(* Logix 5000 Rung export; software revision 16.03; part 2 of 3 *)
(* tags used below, declared in another part *)
   AFC56 : AFC;
   AOI56AFC : AOI56AFC;
(* AOI56AFC, continued *)

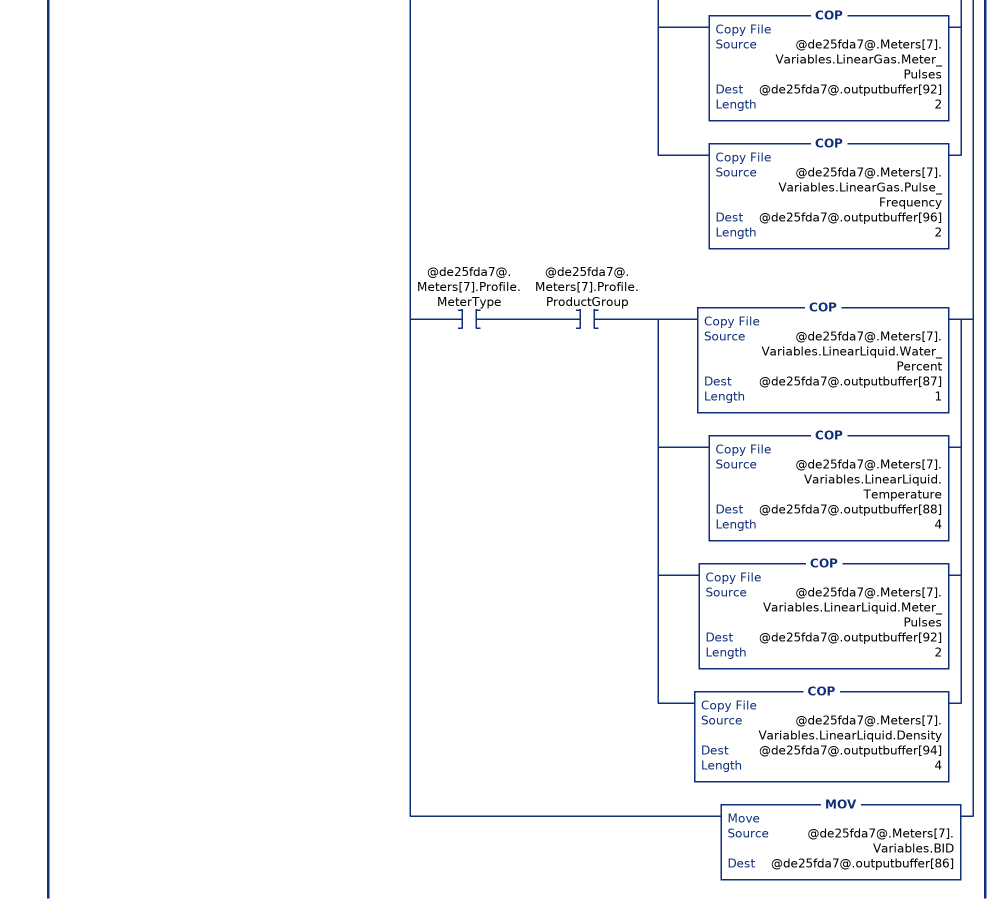
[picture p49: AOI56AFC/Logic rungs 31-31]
   31: XIO(@de25fda7@.Flags.AFC_Set_Clock)LIM(1,@de25fda7@.CycleCounter,16)[ADD(8,8192,@de25fda7@.Meters[7].Variables.BID) ,XIO(@de25fda7@.EnableStatus.Meter8) [OTE(@de25fda7@.Meters[7].Variables.BID.8) ,OTU(@de25fda7@.DisableMeter.Meter8) ] ,XIC(@de25fda7@.EnableStatus.Meter8) OTU(@de25fda7@.EnableMeter.Meter8) ,XIO(@de25fda7@.Meters[7].Profile.MeterType) XIO(@de25fda7@.Meters[7].Profile.ProductGroup) COP(@de25fda7@.Meters[7].Variables.DifferentialGas.Temperature,@de25fda7@.outputbuffer[88],6) ,XIO(@de25fda7@.Meters[7].Profile.MeterType) XIC(@de25fda7@.Meters[7].Profile.ProductGroup) [COP(@de25fda7@.Meters[7].Variables.DifferentialLiquid.Water_Percent,@de25fda7@.outputbuffer[87],1) ,COP(@de25fda7@.Meters[7].Variables.DifferentialLiquid.Temperature,@de25fda7@.outputbuffer[88],8) ] ,XIC(@de25fda7@.Meters[7].Profile.MeterType) XIO(@de25fda7@.Meters[7].Profile.ProductGroup) [COP(@de25fda7@.Meters[7].Variables.LinearGas.Temperature,@de25fda7@.outputbuffer[88],4) ,COP(@de25fda7@.Meters[7].Variables.LinearGas.Meter_Pulses,@de25fda7@.outputbuffer[92],2) ,COP(@de25fda7@.Meters[7].Variables.LinearGas.Pulse_Frequency,@de25fda7@.outputbuffer[96],2) ] ,XIC(@de25fda7@.Meters[7].Profile.MeterType) XIC(@de25fda7@.Meters[7].Profile.ProductGroup) [COP(@de25fda7@.Meters[7].Variables.LinearLiquid.Water_Percent,@de25fda7@.outputbuffer[87],1) ,COP(@de25fda7@.Meters[7].Variables.LinearLiquid.Temperature,@de25fda7@.outputbuffer[88],4) ,COP(@de25fda7@.Meters[7].Variables.LinearLiquid.Meter_Pulses,@de25fda7@.outputbuffer[92],2) ,COP(@de25fda7@.Meters[7].Variables.LinearLiquid.Density,@de25fda7@.outputbuffer[94],4) ] ,MOV(@de25fda7@.Meters[7].Variables.BID,@de25fda7@.outputbuffer[86]) ];
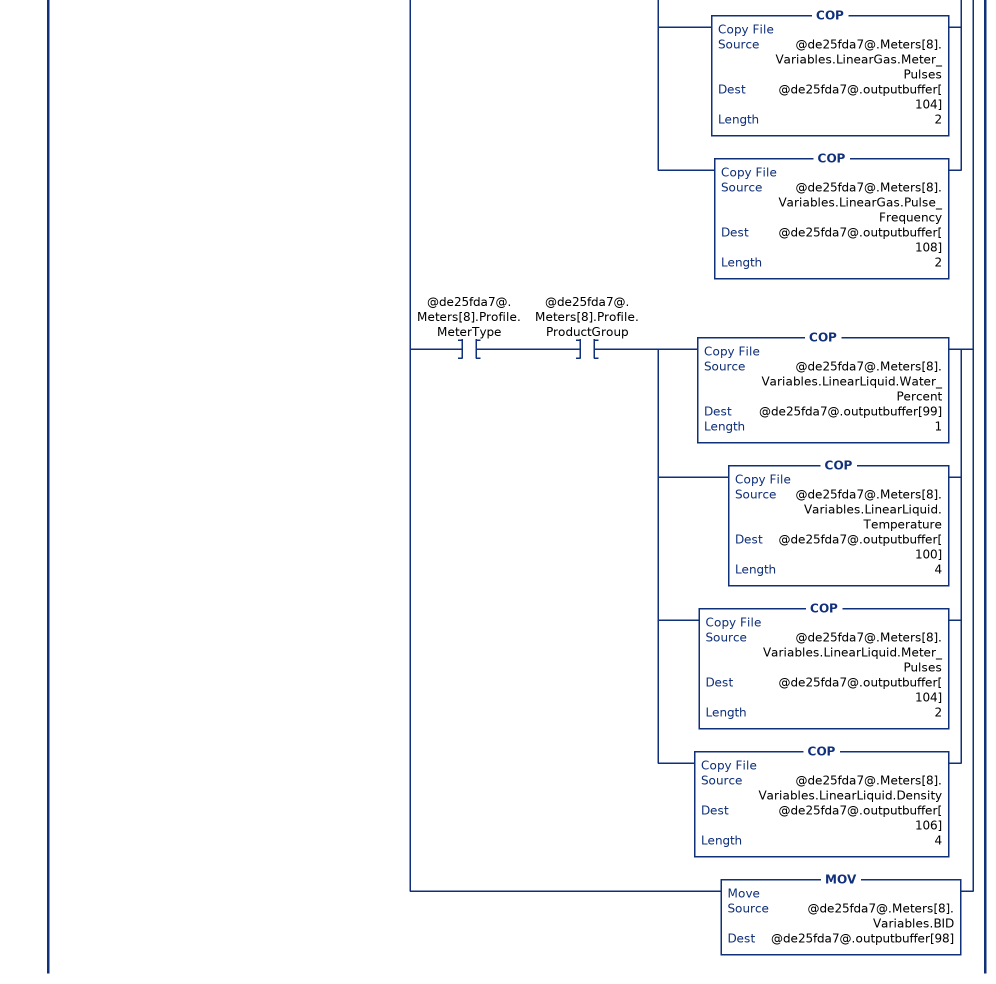
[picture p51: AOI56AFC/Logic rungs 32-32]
   32: XIO(@de25fda7@.Flags.AFC_Set_Clock)LIM(1,@de25fda7@.CycleCounter,16)[ADD(9,8192,@de25fda7@.Meters[8].Variables.BID) ,XIO(@de25fda7@.EnableStatus.Meter9) [OTE(@de25fda7@.Meters[8].Variables.BID.8) ,OTU(@de25fda7@.DisableMeter.Meter9) ] ,XIC(@de25fda7@.EnableStatus.Meter9) OTU(@de25fda7@.EnableMeter.Meter9) ,XIO(@de25fda7@.Meters[8].Profile.MeterType) XIO(@de25fda7@.Meters[8].Profile.ProductGroup) COP(@de25fda7@.Meters[8].Variables.DifferentialGas.Temperature,@de25fda7@.outputbuffer[100],6) ,XIO(@de25fda7@.Meters[8].Profile.MeterType) XIC(@de25fda7@.Meters[8].Profile.ProductGroup) [COP(@de25fda7@.Meters[8].Variables.DifferentialLiquid.Water_Percent,@de25fda7@.outputbuffer[99],1) ,COP(@de25fda7@.Meters[8].Variables.DifferentialLiquid.Temperature,@de25fda7@.outputbuffer[100],8) ] ,XIC(@de25fda7@.Meters[8].Profile.MeterType) XIO(@de25fda7@.Meters[8].Profile.ProductGroup) [COP(@de25fda7@.Meters[8].Variables.LinearGas.Temperature,@de25fda7@.outputbuffer[100],4) ,COP(@de25fda7@.Meters[8].Variables.LinearGas.Meter_Pulses,@de25fda7@.outputbuffer[104],2) ,COP(@de25fda7@.Meters[8].Variables.LinearGas.Pulse_Frequency,@de25fda7@.outputbuffer[108],2) ] ,XIC(@de25fda7@.Meters[8].Profile.MeterType) XIC(@de25fda7@.Meters[8].Profile.ProductGroup) [COP(@de25fda7@.Meters[8].Variables.LinearLiquid.Water_Percent,@de25fda7@.outputbuffer[99],1) ,COP(@de25fda7@.Meters[8].Variables.LinearLiquid.Temperature,@de25fda7@.outputbuffer[100],4) ,COP(@de25fda7@.Meters[8].Variables.LinearLiquid.Meter_Pulses,@de25fda7@.outputbuffer[104],2) ,COP(@de25fda7@.Meters[8].Variables.LinearLiquid.Density,@de25fda7@.outputbuffer[106],4) ] ,MOV(@de25fda7@.Meters[8].Variables.BID,@de25fda7@.outputbuffer[98]) ];
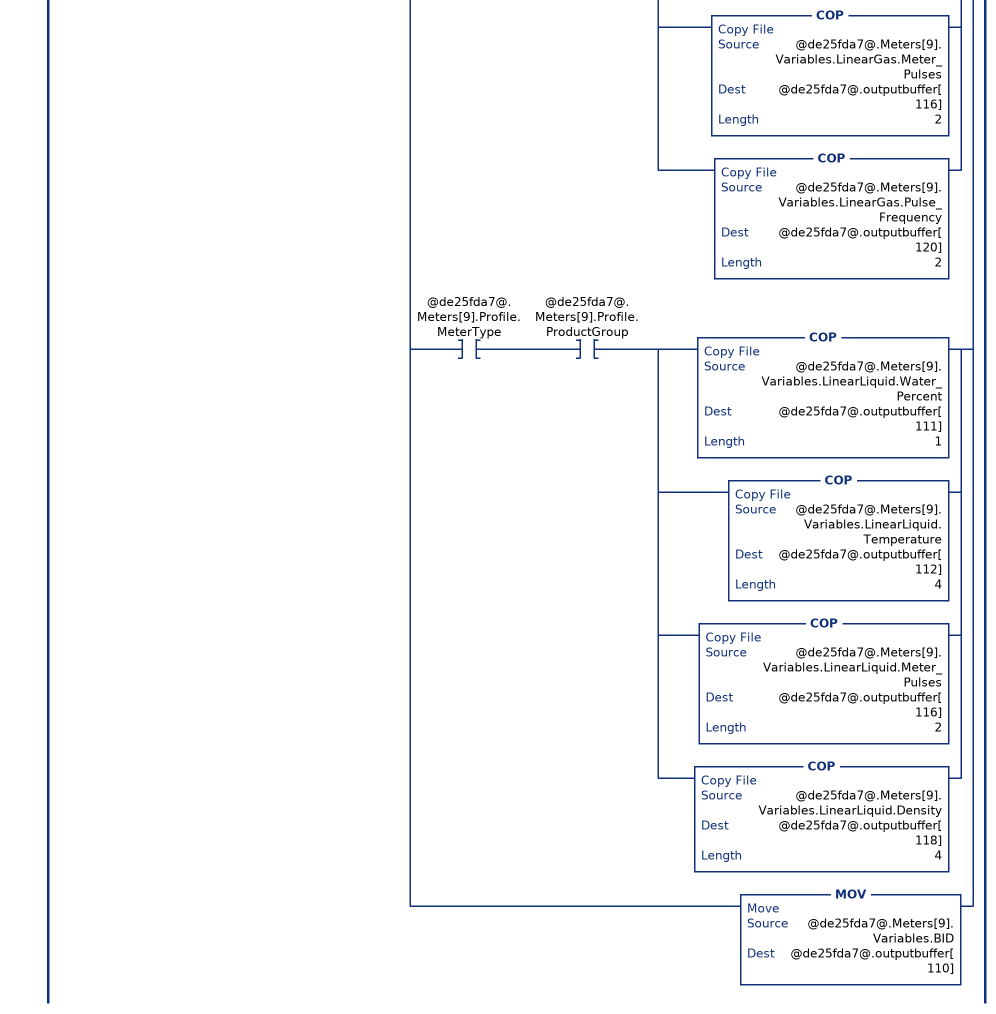
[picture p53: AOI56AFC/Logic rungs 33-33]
   33: XIO(@de25fda7@.Flags.AFC_Set_Clock)LIM(1,@de25fda7@.CycleCounter,16)[ADD(10,8192,@de25fda7@.Meters[9].Variables.BID) ,XIO(@de25fda7@.EnableStatus.Meter10) [OTE(@de25fda7@.Meters[9].Variables.BID.8) ,OTU(@de25fda7@.DisableMeter.Meter10) ] ,XIC(@de25fda7@.EnableStatus.Meter10) OTU(@de25fda7@.EnableMeter.Meter10) ,XIO(@de25fda7@.Meters[9].Profile.MeterType) XIO(@de25fda7@.Meters[9].Profile.ProductGroup) COP(@de25fda7@.Meters[9].Variables.DifferentialGas.Temperature,@de25fda7@.outputbuffer[112],6) ,XIO(@de25fda7@.Meters[9].Profile.MeterType) XIC(@de25fda7@.Meters[9].Profile.ProductGroup) [COP(@de25fda7@.Meters[9].Variables.DifferentialLiquid.Water_Percent,@de25fda7@.outputbuffer[111],1) ,COP(@de25fda7@.Meters[9].Variables.DifferentialLiquid.Temperature,@de25fda7@.outputbuffer[112],8) ] ,XIC(@de25fda7@.Meters[9].Profile.MeterType) XIO(@de25fda7@.Meters[9].Profile.ProductGroup) [COP(@de25fda7@.Meters[9].Variables.LinearGas.Temperature,@de25fda7@.outputbuffer[112],4) ,COP(@de25fda7@.Meters[9].Variables.LinearGas.Meter_Pulses,@de25fda7@.outputbuffer[116],2) ,COP(@de25fda7@.Meters[9].Variables.LinearGas.Pulse_Frequency,@de25fda7@.outputbuffer[120],2) ] ,XIC(@de25fda7@.Meters[9].Profile.MeterType) XIC(@de25fda7@.Meters[9].Profile.ProductGroup) [COP(@de25fda7@.Meters[9].Variables.LinearLiquid.Water_Percent,@de25fda7@.outputbuffer[111],1) ,COP(@de25fda7@.Meters[9].Variables.LinearLiquid.Temperature,@de25fda7@.outputbuffer[112],4) ,COP(@de25fda7@.Meters[9].Variables.LinearLiquid.Meter_Pulses,@de25fda7@.outputbuffer[116],2) ,COP(@de25fda7@.Meters[9].Variables.LinearLiquid.Density,@de25fda7@.outputbuffer[118],4) ] ,MOV(@de25fda7@.Meters[9].Variables.BID,@de25fda7@.outputbuffer[110]) ];
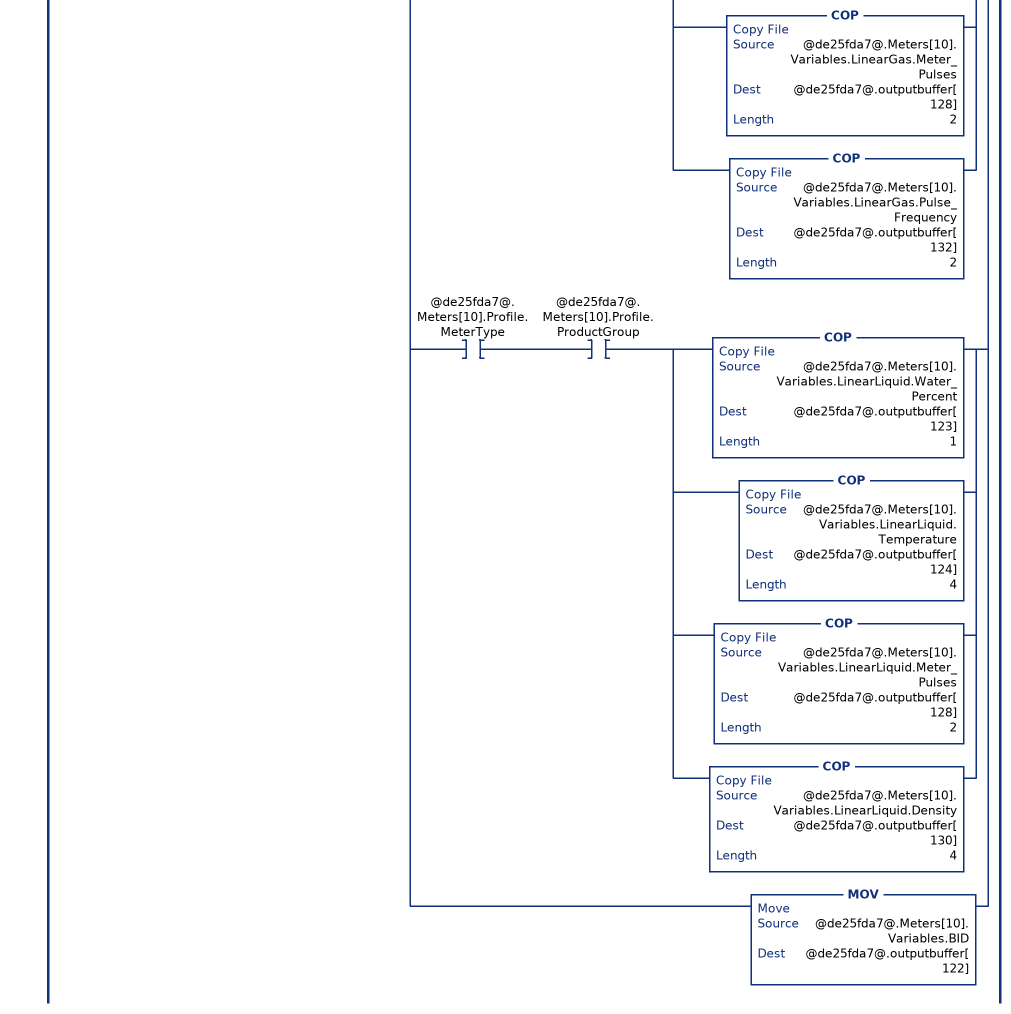
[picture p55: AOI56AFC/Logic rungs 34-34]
   34: XIO(@de25fda7@.Flags.AFC_Set_Clock)LIM(1,@de25fda7@.CycleCounter,16)[ADD(11,8192,@de25fda7@.Meters[10].Variables.BID) ,XIO(@de25fda7@.EnableStatus.Meter11) [OTE(@de25fda7@.Meters[10].Variables.BID.8) ,OTU(@de25fda7@.DisableMeter.Meter11) ] ,XIC(@de25fda7@.EnableStatus.Meter11) OTU(@de25fda7@.EnableMeter.Meter11) ,XIO(@de25fda7@.Meters[10].Profile.MeterType) XIO(@de25fda7@.Meters[10].Profile.ProductGroup) COP(@de25fda7@.Meters[10].Variables.DifferentialGas.Temperature,@de25fda7@.outputbuffer[124],6) ,XIO(@de25fda7@.Meters[10].Profile.MeterType) XIC(@de25fda7@.Meters[10].Profile.ProductGroup) [COP(@de25fda7@.Meters[10].Variables.DifferentialLiquid.Water_Percent,@de25fda7@.outputbuffer[123],1) ,COP(@de25fda7@.Meters[10].Variables.DifferentialLiquid.Temperature,@de25fda7@.outputbuffer[124],8) ] ,XIC(@de25fda7@.Meters[10].Profile.MeterType) XIO(@de25fda7@.Meters[10].Profile.ProductGroup) [COP(@de25fda7@.Meters[10].Variables.LinearGas.Temperature,@de25fda7@.outputbuffer[124],4) ,COP(@de25fda7@.Meters[10].Variables.LinearGas.Meter_Pulses,@de25fda7@.outputbuffer[128],2) ,COP(@de25fda7@.Meters[10].Variables.LinearGas.Pulse_Frequency,@de25fda7@.outputbuffer[132],2) ] ,XIC(@de25fda7@.Meters[10].Profile.MeterType) XIC(@de25fda7@.Meters[10].Profile.ProductGroup) [COP(@de25fda7@.Meters[10].Variables.LinearLiquid.Water_Percent,@de25fda7@.outputbuffer[123],1) ,COP(@de25fda7@.Meters[10].Variables.LinearLiquid.Temperature,@de25fda7@.outputbuffer[124],4) ,COP(@de25fda7@.Meters[10].Variables.LinearLiquid.Meter_Pulses,@de25fda7@.outputbuffer[128],2) ,COP(@de25fda7@.Meters[10].Variables.LinearLiquid.Density,@de25fda7@.outputbuffer[130],4) ] ,MOV(@de25fda7@.Meters[10].Variables.BID,@de25fda7@.outputbuffer[122]) ];
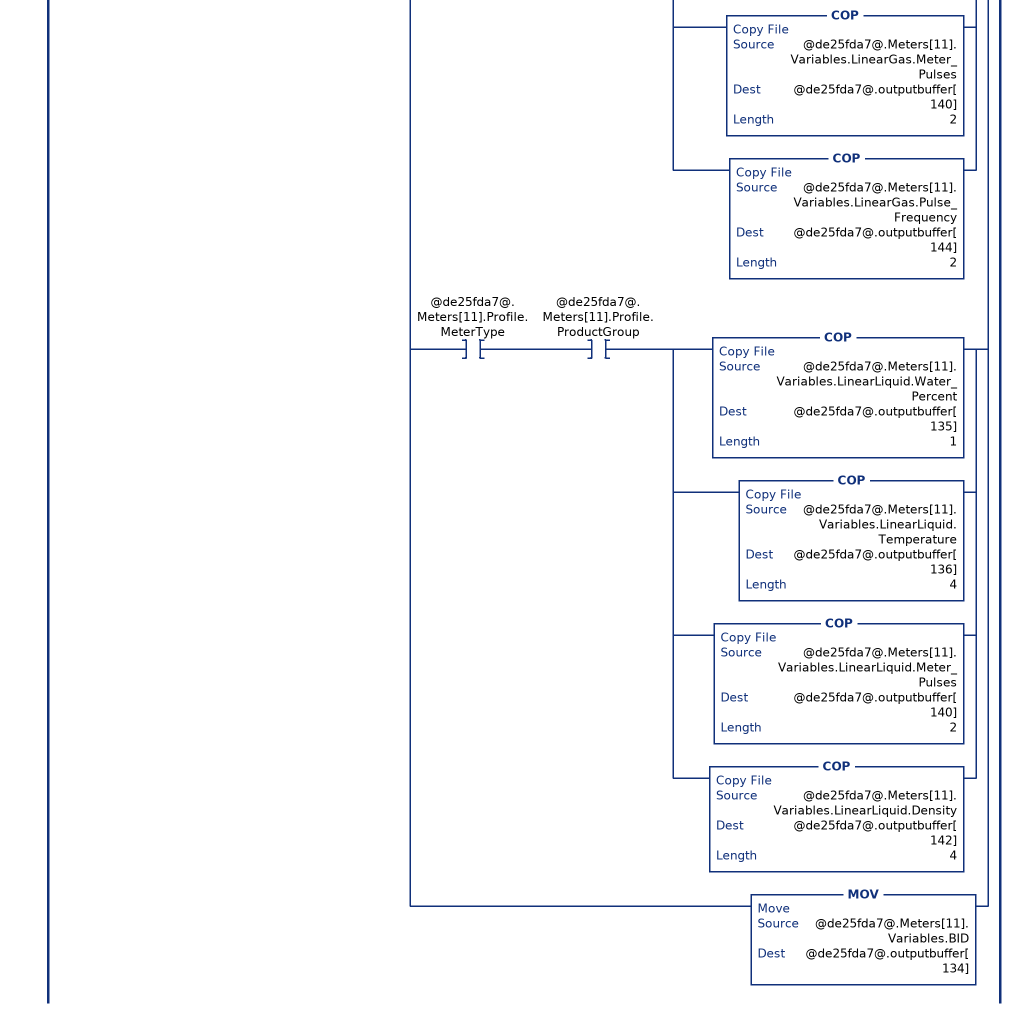
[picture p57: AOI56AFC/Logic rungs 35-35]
   35: XIO(@de25fda7@.Flags.AFC_Set_Clock)LIM(1,@de25fda7@.CycleCounter,16)[ADD(12,8192,@de25fda7@.Meters[11].Variables.BID) ,XIO(@de25fda7@.EnableStatus.Meter12) [OTE(@de25fda7@.Meters[11].Variables.BID.8) ,OTU(@de25fda7@.DisableMeter.Meter12) ] ,XIC(@de25fda7@.EnableStatus.Meter12) OTU(@de25fda7@.EnableMeter.Meter12) ,XIO(@de25fda7@.Meters[11].Profile.MeterType) XIO(@de25fda7@.Meters[11].Profile.ProductGroup) COP(@de25fda7@.Meters[11].Variables.DifferentialGas.Temperature,@de25fda7@.outputbuffer[136],6) ,XIO(@de25fda7@.Meters[11].Profile.MeterType) XIC(@de25fda7@.Meters[11].Profile.ProductGroup) [COP(@de25fda7@.Meters[11].Variables.DifferentialLiquid.Water_Percent,@de25fda7@.outputbuffer[135],1) ,COP(@de25fda7@.Meters[11].Variables.DifferentialLiquid.Temperature,@de25fda7@.outputbuffer[136],8) ] ,XIC(@de25fda7@.Meters[11].Profile.MeterType) XIO(@de25fda7@.Meters[11].Profile.ProductGroup) [COP(@de25fda7@.Meters[11].Variables.LinearGas.Temperature,@de25fda7@.outputbuffer[136],4) ,COP(@de25fda7@.Meters[11].Variables.LinearGas.Meter_Pulses,@de25fda7@.outputbuffer[140],2) ,COP(@de25fda7@.Meters[11].Variables.LinearGas.Pulse_Frequency,@de25fda7@.outputbuffer[144],2) ] ,XIC(@de25fda7@.Meters[11].Profile.MeterType) XIC(@de25fda7@.Meters[11].Profile.ProductGroup) [COP(@de25fda7@.Meters[11].Variables.LinearLiquid.Water_Percent,@de25fda7@.outputbuffer[135],1) ,COP(@de25fda7@.Meters[11].Variables.LinearLiquid.Temperature,@de25fda7@.outputbuffer[136],4) ,COP(@de25fda7@.Meters[11].Variables.LinearLiquid.Meter_Pulses,@de25fda7@.outputbuffer[140],2) ,COP(@de25fda7@.Meters[11].Variables.LinearLiquid.Density,@de25fda7@.outputbuffer[142],4) ] ,MOV(@de25fda7@.Meters[11].Variables.BID,@de25fda7@.outputbuffer[134]) ];
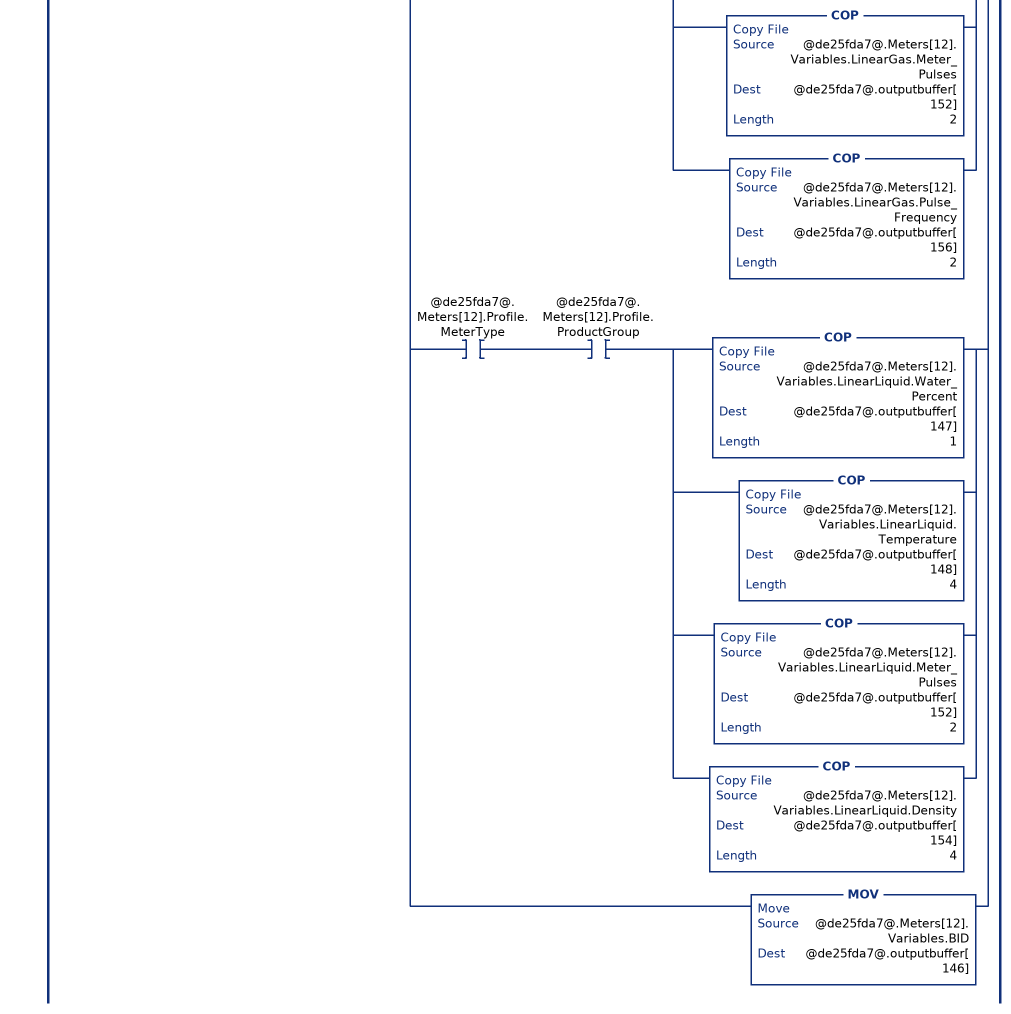
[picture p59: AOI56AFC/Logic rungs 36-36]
   36: XIO(@de25fda7@.Flags.AFC_Set_Clock)LIM(1,@de25fda7@.CycleCounter,16)[ADD(13,8192,@de25fda7@.Meters[12].Variables.BID) ,XIO(@de25fda7@.EnableStatus.Meter13) [OTE(@de25fda7@.Meters[12].Variables.BID.8) ,OTU(@de25fda7@.DisableMeter.Meter13) ] ,XIC(@de25fda7@.EnableStatus.Meter13) OTU(@de25fda7@.EnableMeter.Meter13) ,XIO(@de25fda7@.Meters[12].Profile.MeterType) XIO(@de25fda7@.Meters[12].Profile.ProductGroup) COP(@de25fda7@.Meters[12].Variables.DifferentialGas.Temperature,@de25fda7@.outputbuffer[148],6) ,XIO(@de25fda7@.Meters[12].Profile.MeterType) XIC(@de25fda7@.Meters[12].Profile.ProductGroup) [COP(@de25fda7@.Meters[12].Variables.DifferentialLiquid.Water_Percent,@de25fda7@.outputbuffer[147],1) ,COP(@de25fda7@.Meters[12].Variables.DifferentialLiquid.Temperature,@de25fda7@.outputbuffer[148],8) ] ,XIC(@de25fda7@.Meters[12].Profile.MeterType) XIO(@de25fda7@.Meters[12].Profile.ProductGroup) [COP(@de25fda7@.Meters[12].Variables.LinearGas.Temperature,@de25fda7@.outputbuffer[148],4) ,COP(@de25fda7@.Meters[12].Variables.LinearGas.Meter_Pulses,@de25fda7@.outputbuffer[152],2) ,COP(@de25fda7@.Meters[12].Variables.LinearGas.Pulse_Frequency,@de25fda7@.outputbuffer[156],2) ] ,XIC(@de25fda7@.Meters[12].Profile.MeterType) XIC(@de25fda7@.Meters[12].Profile.ProductGroup) [COP(@de25fda7@.Meters[12].Variables.LinearLiquid.Water_Percent,@de25fda7@.outputbuffer[147],1) ,COP(@de25fda7@.Meters[12].Variables.LinearLiquid.Temperature,@de25fda7@.outputbuffer[148],4) ,COP(@de25fda7@.Meters[12].Variables.LinearLiquid.Meter_Pulses,@de25fda7@.outputbuffer[152],2) ,COP(@de25fda7@.Meters[12].Variables.LinearLiquid.Density,@de25fda7@.outputbuffer[154],4) ] ,MOV(@de25fda7@.Meters[12].Variables.BID,@de25fda7@.outputbuffer[146]) ];
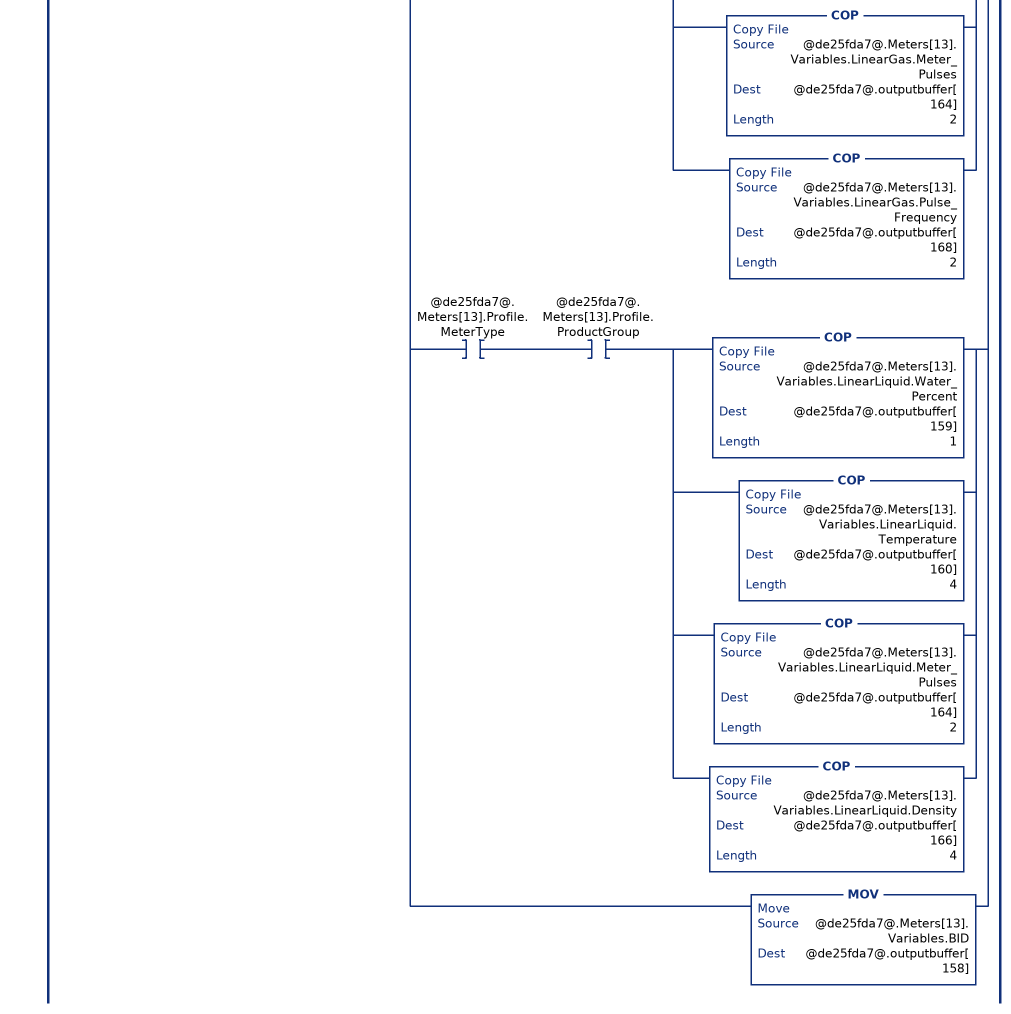
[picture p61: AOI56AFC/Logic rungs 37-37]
   37: XIO(@de25fda7@.Flags.AFC_Set_Clock)LIM(1,@de25fda7@.CycleCounter,16)[ADD(14,8192,@de25fda7@.Meters[13].Variables.BID) ,XIO(@de25fda7@.EnableStatus.Meter14) [OTE(@de25fda7@.Meters[13].Variables.BID.8) ,OTU(@de25fda7@.DisableMeter.Meter14) ] ,XIC(@de25fda7@.EnableStatus.Meter14) OTU(@de25fda7@.EnableMeter.Meter14) ,XIO(@de25fda7@.Meters[13].Profile.MeterType) XIO(@de25fda7@.Meters[13].Profile.ProductGroup) COP(@de25fda7@.Meters[13].Variables.DifferentialGas.Temperature,@de25fda7@.outputbuffer[160],6) ,XIO(@de25fda7@.Meters[13].Profile.MeterType) XIC(@de25fda7@.Meters[13].Profile.ProductGroup) [COP(@de25fda7@.Meters[13].Variables.DifferentialLiquid.Water_Percent,@de25fda7@.outputbuffer[159],1) ,COP(@de25fda7@.Meters[13].Variables.DifferentialLiquid.Temperature,@de25fda7@.outputbuffer[160],8) ] ,XIC(@de25fda7@.Meters[13].Profile.MeterType) XIO(@de25fda7@.Meters[13].Profile.ProductGroup) [COP(@de25fda7@.Meters[13].Variables.LinearGas.Temperature,@de25fda7@.outputbuffer[160],4) ,COP(@de25fda7@.Meters[13].Variables.LinearGas.Meter_Pulses,@de25fda7@.outputbuffer[164],2) ,COP(@de25fda7@.Meters[13].Variables.LinearGas.Pulse_Frequency,@de25fda7@.outputbuffer[168],2) ] ,XIC(@de25fda7@.Meters[13].Profile.MeterType) XIC(@de25fda7@.Meters[13].Profile.ProductGroup) [COP(@de25fda7@.Meters[13].Variables.LinearLiquid.Water_Percent,@de25fda7@.outputbuffer[159],1) ,COP(@de25fda7@.Meters[13].Variables.LinearLiquid.Temperature,@de25fda7@.outputbuffer[160],4) ,COP(@de25fda7@.Meters[13].Variables.LinearLiquid.Meter_Pulses,@de25fda7@.outputbuffer[164],2) ,COP(@de25fda7@.Meters[13].Variables.LinearLiquid.Density,@de25fda7@.outputbuffer[166],4) ] ,MOV(@de25fda7@.Meters[13].Variables.BID,@de25fda7@.outputbuffer[158]) ];
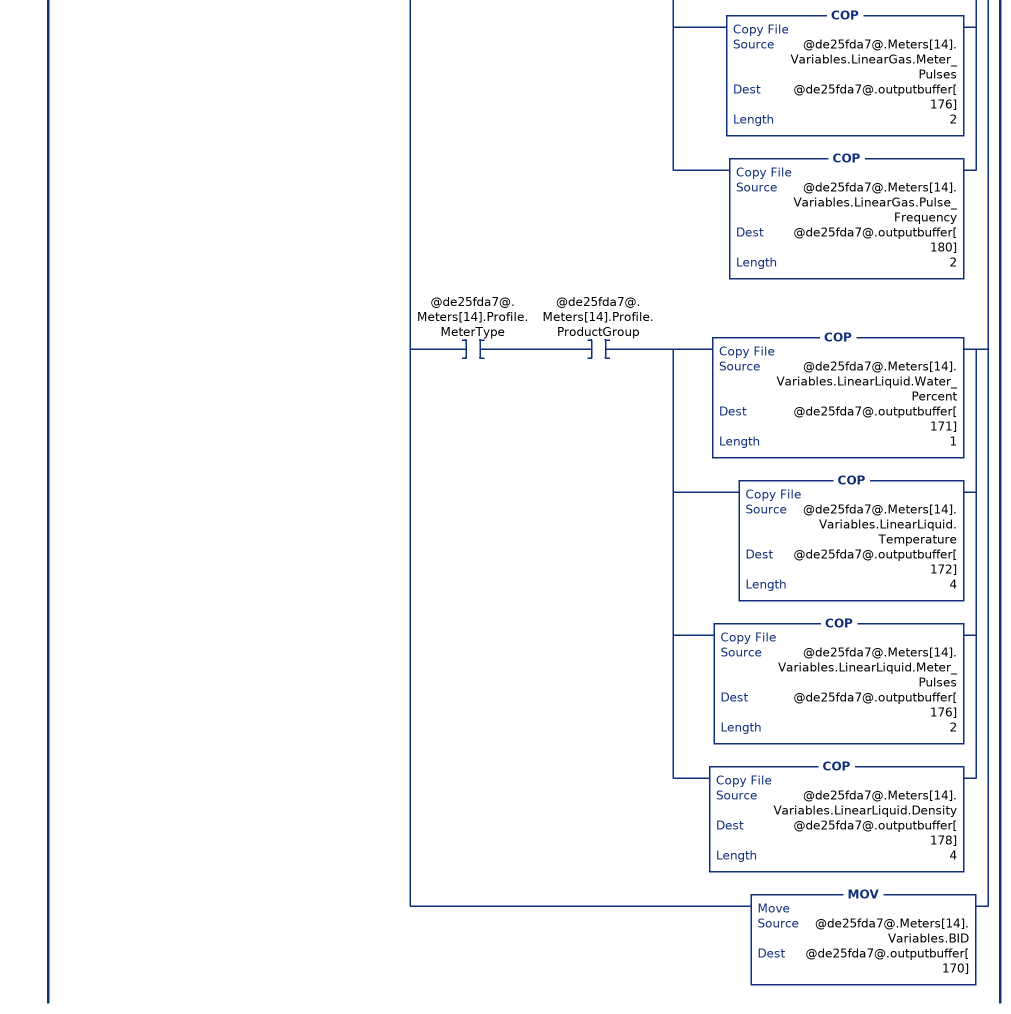
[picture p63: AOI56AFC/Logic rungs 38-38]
   38: XIO(@de25fda7@.Flags.AFC_Set_Clock)LIM(1,@de25fda7@.CycleCounter,16)[ADD(15,8192,@de25fda7@.Meters[14].Variables.BID) ,XIO(@de25fda7@.EnableStatus.Meter15) [OTE(@de25fda7@.Meters[14].Variables.BID.8) ,OTU(@de25fda7@.DisableMeter.Meter15) ] ,XIC(@de25fda7@.EnableStatus.Meter15) OTU(@de25fda7@.EnableMeter.Meter15) ,XIO(@de25fda7@.Meters[14].Profile.MeterType) XIO(@de25fda7@.Meters[14].Profile.ProductGroup) COP(@de25fda7@.Meters[14].Variables.DifferentialGas.Temperature,@de25fda7@.outputbuffer[172],6) ,XIO(@de25fda7@.Meters[14].Profile.MeterType) XIC(@de25fda7@.Meters[14].Profile.ProductGroup) [COP(@de25fda7@.Meters[14].Variables.DifferentialLiquid.Water_Percent,@de25fda7@.outputbuffer[171],1) ,COP(@de25fda7@.Meters[14].Variables.DifferentialLiquid.Temperature,@de25fda7@.outputbuffer[172],8) ] ,XIC(@de25fda7@.Meters[14].Profile.MeterType) XIO(@de25fda7@.Meters[14].Profile.ProductGroup) [COP(@de25fda7@.Meters[14].Variables.LinearGas.Temperature,@de25fda7@.outputbuffer[172],4) ,COP(@de25fda7@.Meters[14].Variables.LinearGas.Meter_Pulses,@de25fda7@.outputbuffer[176],2) ,COP(@de25fda7@.Meters[14].Variables.LinearGas.Pulse_Frequency,@de25fda7@.outputbuffer[180],2) ] ,XIC(@de25fda7@.Meters[14].Profile.MeterType) XIC(@de25fda7@.Meters[14].Profile.ProductGroup) [COP(@de25fda7@.Meters[14].Variables.LinearLiquid.Water_Percent,@de25fda7@.outputbuffer[171],1) ,COP(@de25fda7@.Meters[14].Variables.LinearLiquid.Temperature,@de25fda7@.outputbuffer[172],4) ,COP(@de25fda7@.Meters[14].Variables.LinearLiquid.Meter_Pulses,@de25fda7@.outputbuffer[176],2) ,COP(@de25fda7@.Meters[14].Variables.LinearLiquid.Density,@de25fda7@.outputbuffer[178],4) ] ,MOV(@de25fda7@.Meters[14].Variables.BID,@de25fda7@.outputbuffer[170]) ];
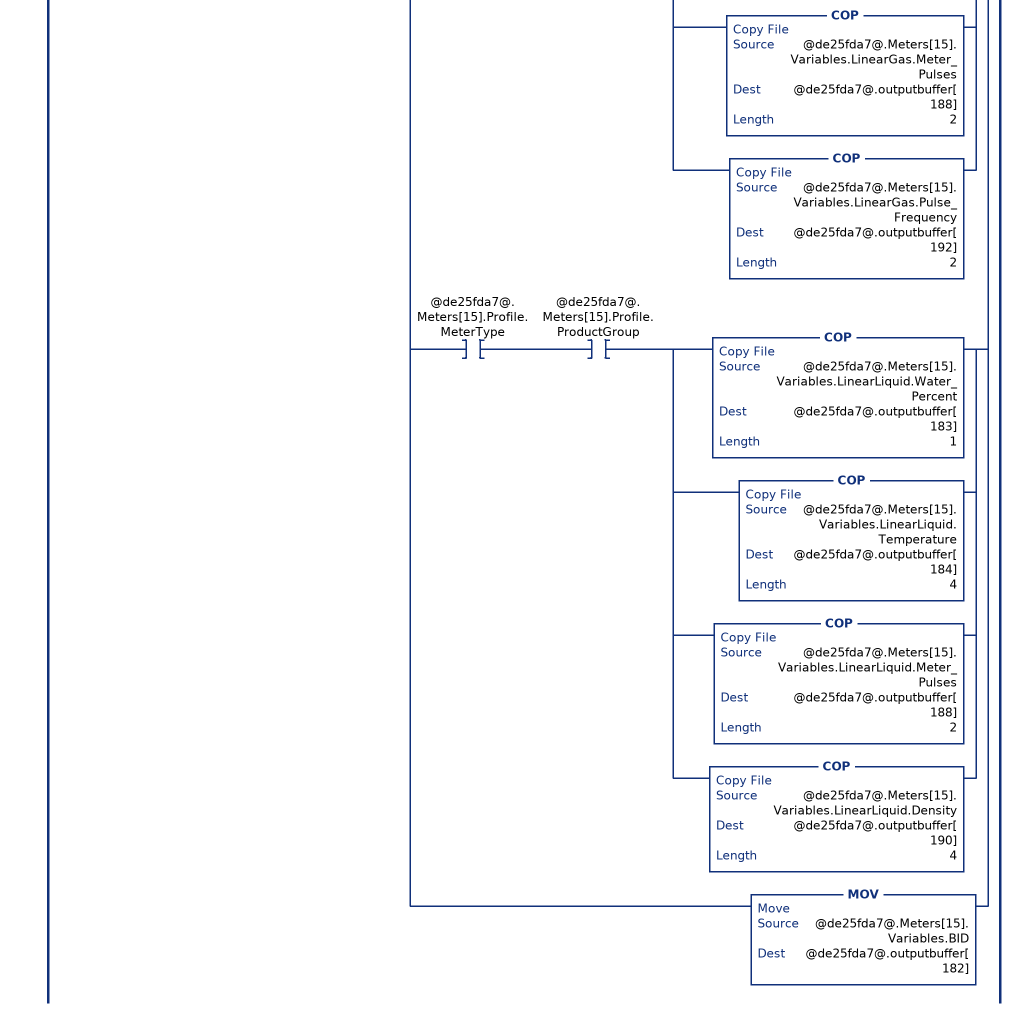
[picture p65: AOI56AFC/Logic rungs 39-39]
   39: XIO(@de25fda7@.Flags.AFC_Set_Clock)LIM(1,@de25fda7@.CycleCounter,16)[ADD(16,8192,@de25fda7@.Meters[15].Variables.BID) ,XIO(@de25fda7@.EnableStatus.Meter16) [OTE(@de25fda7@.Meters[15].Variables.BID.8) ,OTU(@de25fda7@.DisableMeter.Meter16) ] ,XIC(@de25fda7@.EnableStatus.Meter16) OTU(@de25fda7@.EnableMeter.Meter16) ,XIO(@de25fda7@.Meters[15].Profile.MeterType) XIO(@de25fda7@.Meters[15].Profile.ProductGroup) COP(@de25fda7@.Meters[15].Variables.DifferentialGas.Temperature,@de25fda7@.outputbuffer[184],6) ,XIO(@de25fda7@.Meters[15].Profile.MeterType) XIC(@de25fda7@.Meters[15].Profile.ProductGroup) [COP(@de25fda7@.Meters[15].Variables.DifferentialLiquid.Water_Percent,@de25fda7@.outputbuffer[183],1) ,COP(@de25fda7@.Meters[15].Variables.DifferentialLiquid.Temperature,@de25fda7@.outputbuffer[184],8) ] ,XIC(@de25fda7@.Meters[15].Profile.MeterType) XIO(@de25fda7@.Meters[15].Profile.ProductGroup) [COP(@de25fda7@.Meters[15].Variables.LinearGas.Temperature,@de25fda7@.outputbuffer[184],4) ,COP(@de25fda7@.Meters[15].Variables.LinearGas.Meter_Pulses,@de25fda7@.outputbuffer[188],2) ,COP(@de25fda7@.Meters[15].Variables.LinearGas.Pulse_Frequency,@de25fda7@.outputbuffer[192],2) ] ,XIC(@de25fda7@.Meters[15].Profile.MeterType) XIC(@de25fda7@.Meters[15].Profile.ProductGroup) [COP(@de25fda7@.Meters[15].Variables.LinearLiquid.Water_Percent,@de25fda7@.outputbuffer[183],1) ,COP(@de25fda7@.Meters[15].Variables.LinearLiquid.Temperature,@de25fda7@.outputbuffer[184],4) ,COP(@de25fda7@.Meters[15].Variables.LinearLiquid.Meter_Pulses,@de25fda7@.outputbuffer[188],2) ,COP(@de25fda7@.Meters[15].Variables.LinearLiquid.Density,@de25fda7@.outputbuffer[190],4) ] ,MOV(@de25fda7@.Meters[15].Variables.BID,@de25fda7@.outputbuffer[182]) ];
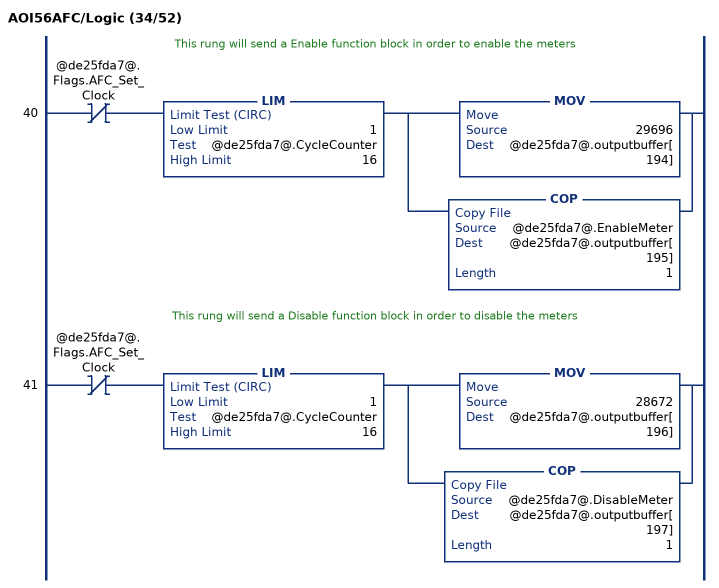
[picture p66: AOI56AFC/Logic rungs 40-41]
   // This rung will send a Enable function block in order to enable the meters
   40: XIO(@de25fda7@.Flags.AFC_Set_Clock)LIM(1,@de25fda7@.CycleCounter,16)[MOV(29696,@de25fda7@.outputbuffer[194]) ,COP(@de25fda7@.EnableMeter,@de25fda7@.outputbuffer[195],1) ];
   // This rung will send a Disable function block in order to disable the meters
   41: XIO(@de25fda7@.Flags.AFC_Set_Clock)LIM(1,@de25fda7@.CycleCounter,16)[MOV(28672,@de25fda7@.outputbuffer[196]) ,COP(@de25fda7@.DisableMeter,@de25fda7@.outputbuffer[197],1) ];
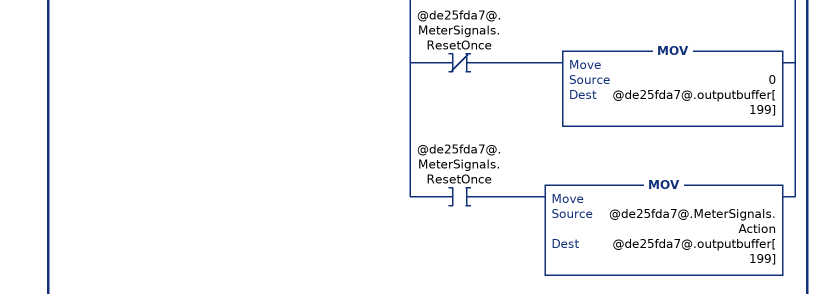
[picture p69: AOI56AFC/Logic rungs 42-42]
   // This rung will allow the ladder logic to reset any accumulator or to write a daily or hourly archive
   42: XIO(@de25fda7@.Flags.AFC_Set_Clock)LIM(1,@de25fda7@.CycleCounter,16)[ADD(12288,@de25fda7@.MeterSignals.Meter,@de25fda7@.MeterSignals.BID) ,XIO(@de25fda7@.MeterSignals.Enable) OTE(@de25fda7@.MeterSignals.BID.8) ,XIC(@de25fda7@.MeterSignals.Signals.Sel_Stream1) [OTL(@de25fda7@.MeterSignals.Action.0) ,OTU(@de25fda7@.MeterSignals.Signals.Sel_Stream1) ] ,XIC(@de25fda7@.MeterSignals.Signals.Sel_Stream2) [OTL(@de25fda7@.MeterSignals.Action.1) ,OTU(@de25fda7@.MeterSignals.Signals.Sel_Stream2) ] ,XIC(@de25fda7@.MeterSignals.Signals.Sel_Stream3) [OTL(@de25fda7@.MeterSignals.Action.2) ,OTU(@de25fda7@.MeterSignals.Signals.Sel_Stream3) ] ,XIC(@de25fda7@.MeterSignals.Signals.Sel_Stream4) [OTL(@de25fda7@.MeterSignals.Action.3) ,OTU(@de25fda7@.MeterSignals.Signals.Sel_Stream4) ] ,XIC(@de25fda7@.MeterSignals.Signals.Res_Acc1) [OTL(@de25fda7@.MeterSignals.Action.4) ,OTU(@de25fda7@.MeterSignals.Signals.Res_Acc1) ] ,XIC(@de25fda7@.MeterSignals.Signals.Res_Acc2) [OTL(@de25fda7@.MeterSignals.Action.5) ,OTU(@de25fda7@.MeterSignals.Signals.Res_Acc2) ] ,XIC(@de25fda7@.MeterSignals.Signals.Res_Acc3) [OTL(@de25fda7@.MeterSignals.Action.6) ,OTU(@de25fda7@.MeterSignals.Signals.Res_Acc3) ] ,XIC(@de25fda7@.MeterSignals.Signals.Res_Acc4) [OTL(@de25fda7@.MeterSignals.Action.7) ,OTU(@de25fda7@.MeterSignals.Signals.Res_Acc4) ] ,XIC(@de25fda7@.MeterSignals.Signals.Wr_Daily_Archive) [OTL(@de25fda7@.MeterSignals.Action.8) ,OTU(@de25fda7@.MeterSignals.Signals.Wr_Daily_Archive) ] ,XIC(@de25fda7@.MeterSignals.Signals.Wr_Hrly_Archive) [OTL(@de25fda7@.MeterSignals.Action.9) ,OTU(@de25fda7@.MeterSignals.Signals.Wr_Hrly_Archive) ] ,MOV(@de25fda7@.MeterSignals.BID,@de25fda7@.outputbuffer[198]) ,XIO(@de25fda7@.MeterSignals.ResetOnce) MOV(0,@de25fda7@.outputbuffer[199]) ,XIC(@de25fda7@.MeterSignals.ResetOnce) MOV(@de25fda7@.MeterSignals.Action,@de25fda7@.outputbuffer[199]) ];
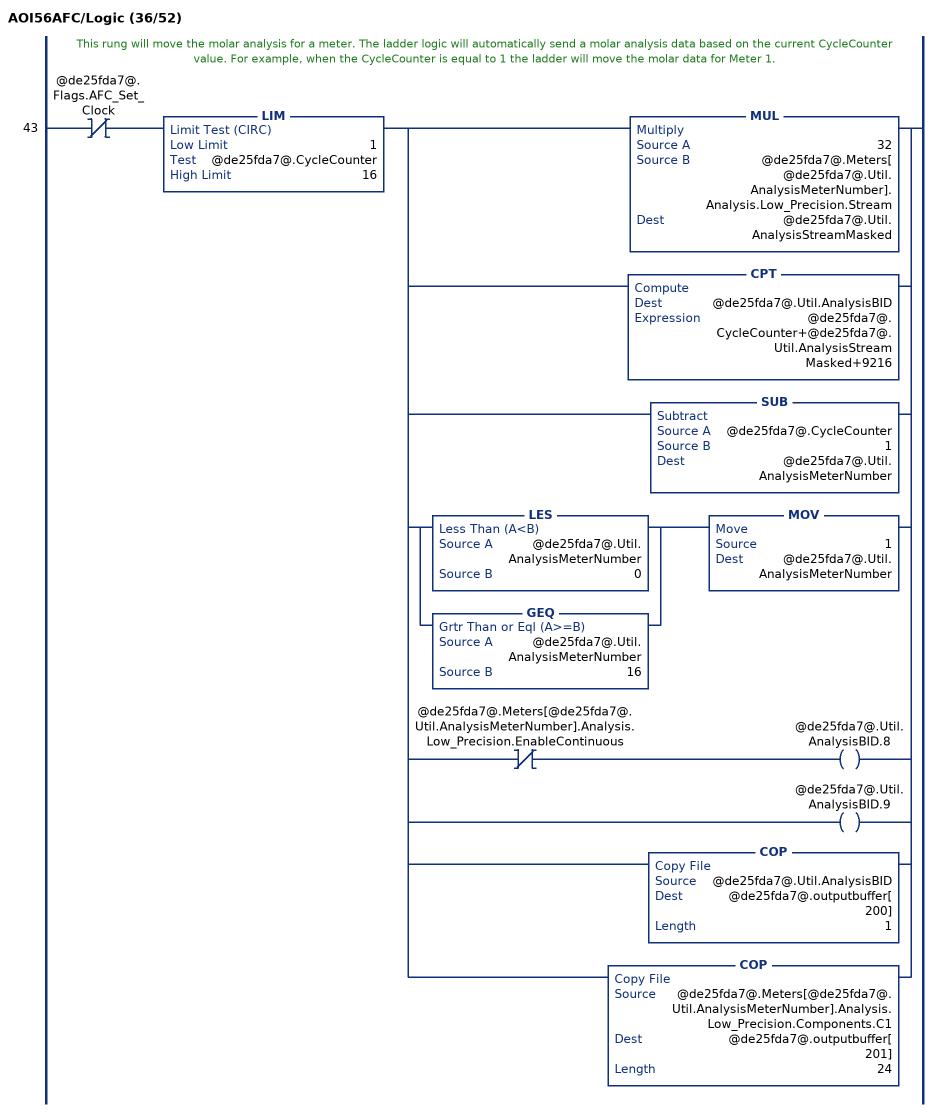
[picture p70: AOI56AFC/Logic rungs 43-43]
   // This rung will move the molar analysis for a meter. The ladder logic will automatically send a molar analysis data based on the current CycleCounter value. For example, when the CycleCounter is equal to 1 the ladder will move the molar data for Meter 1.
   43: XIO(@de25fda7@.Flags.AFC_Set_Clock)LIM(1,@de25fda7@.CycleCounter,16)[MUL(32,@de25fda7@.Meters[@de25fda7@.Util.AnalysisMeterNumber].Analysis.Low_Precision.Stream,@de25fda7@.Util.AnalysisStreamMasked) ,CPT(@de25fda7@.Util.AnalysisBID,@de25fda7@.CycleCounter+@de25fda7@.Util.AnalysisStreamMasked+9216) ,SUB(@de25fda7@.CycleCounter,1,@de25fda7@.Util.AnalysisMeterNumber) ,[LES(@de25fda7@.Util.AnalysisMeterNumber,0) ,GEQ(@de25fda7@.Util.AnalysisMeterNumber,16) ] MOV(1,@de25fda7@.Util.AnalysisMeterNumber) ,XIO(@de25fda7@.Meters[@de25fda7@.Util.AnalysisMeterNumber].Analysis.Low_Precision.EnableContinuous) OTE(@de25fda7@.Util.AnalysisBID.8) ,OTE(@de25fda7@.Util.AnalysisBID.9) ,COP(@de25fda7@.Util.AnalysisBID,@de25fda7@.outputbuffer[200],1) ,COP(@de25fda7@.Meters[@de25fda7@.Util.AnalysisMeterNumber].Analysis.Low_Precision.Components.C1,@de25fda7@.outputbuffer[201],24) ];
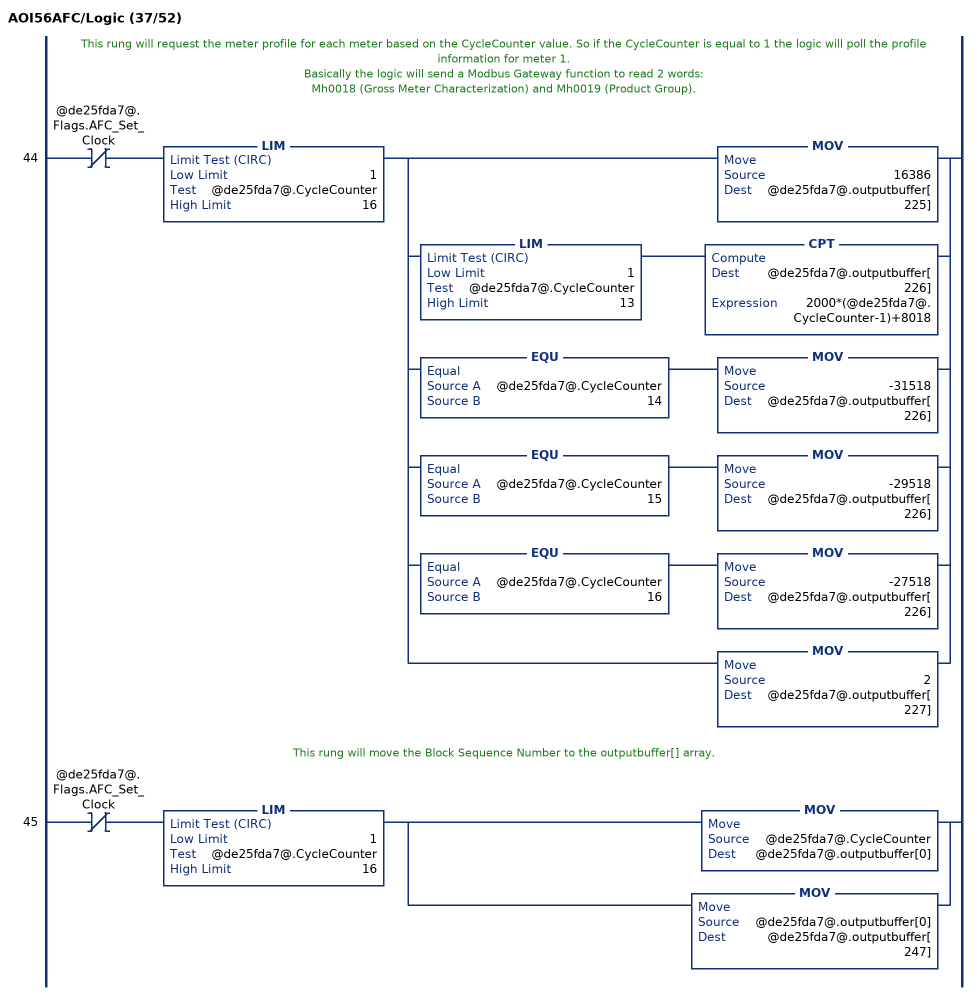
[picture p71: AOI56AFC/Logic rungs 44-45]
   // This rung will request the meter profile for each meter based on the CycleCounter value. So if the CycleCounter is equal to 1 the logic will poll the profile information for meter 1.
   // Basically the logic will send a Modbus Gateway function to read 2 words:
   // Mh0018 (Gross Meter Characterization) and Mh0019 (Product Group).
   44: XIO(@de25fda7@.Flags.AFC_Set_Clock)LIM(1,@de25fda7@.CycleCounter,16)[MOV(16386,@de25fda7@.outputbuffer[225]) ,LIM(1,@de25fda7@.CycleCounter,13) CPT(@de25fda7@.outputbuffer[226],2000*(@de25fda7@.CycleCounter-1)+8018) ,EQU(@de25fda7@.CycleCounter,14) MOV(-31518,@de25fda7@.outputbuffer[226]) ,EQU(@de25fda7@.CycleCounter,15) MOV(-29518,@de25fda7@.outputbuffer[226]) ,EQU(@de25fda7@.CycleCounter,16) MOV(-27518,@de25fda7@.outputbuffer[226]) ,MOV(2,@de25fda7@.outputbuffer[227]) ];
   // This rung will move the Block Sequence Number to the outputbuffer[] array.
   45: XIO(@de25fda7@.Flags.AFC_Set_Clock)LIM(1,@de25fda7@.CycleCounter,16)[MOV(@de25fda7@.CycleCounter,@de25fda7@.outputbuffer[0]) ,MOV(@de25fda7@.outputbuffer[0],@de25fda7@.outputbuffer[247]) ];
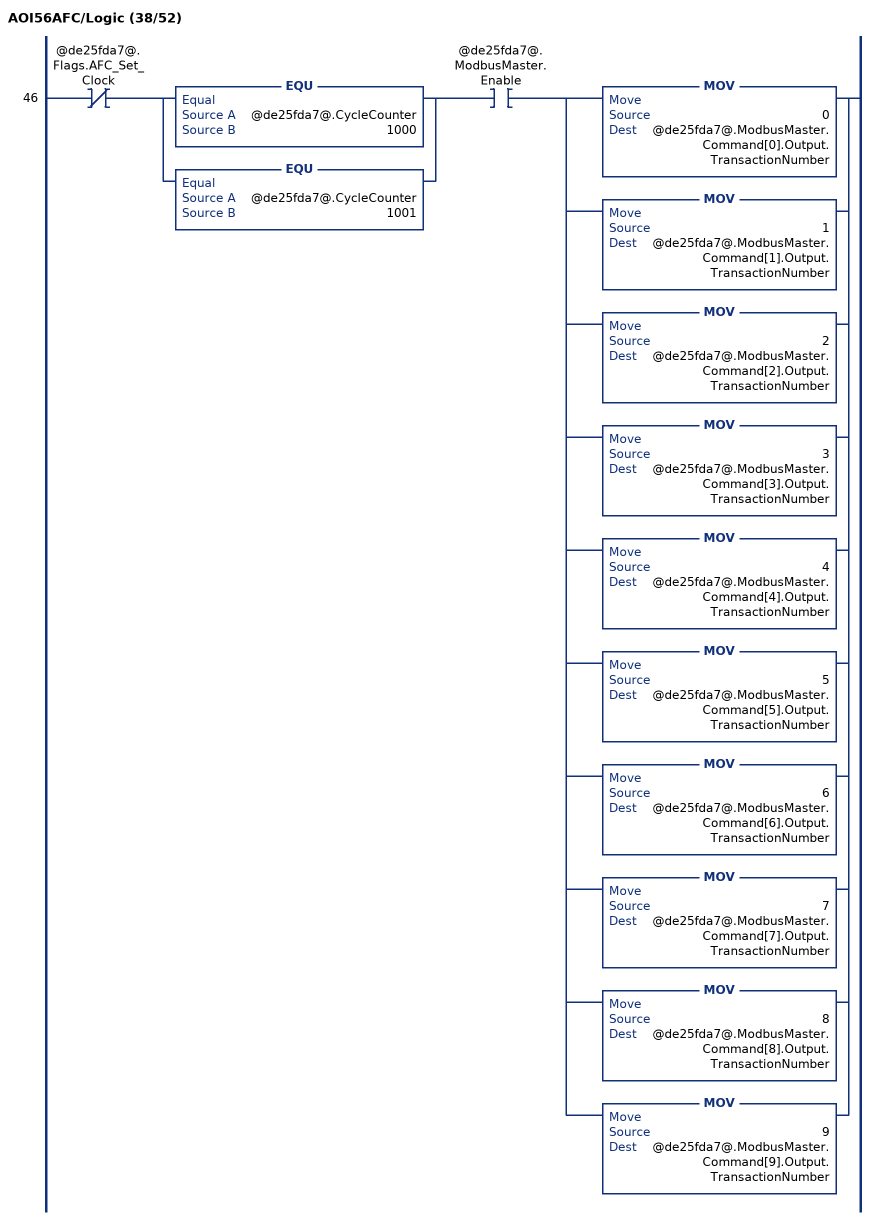
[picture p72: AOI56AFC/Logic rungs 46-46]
   46: XIO(@de25fda7@.Flags.AFC_Set_Clock)[EQU(@de25fda7@.CycleCounter,1000) ,EQU(@de25fda7@.CycleCounter,1001) ]XIC(@de25fda7@.ModbusMaster.Enable)[MOV(0,@de25fda7@.ModbusMaster.Command[0].Output.TransactionNumber) ,MOV(1,@de25fda7@.ModbusMaster.Command[1].Output.TransactionNumber) ,MOV(2,@de25fda7@.ModbusMaster.Command[2].Output.TransactionNumber) ,MOV(3,@de25fda7@.ModbusMaster.Command[3].Output.TransactionNumber) ,MOV(4,@de25fda7@.ModbusMaster.Command[4].Output.TransactionNumber) ,MOV(5,@de25fda7@.ModbusMaster.Command[5].Output.TransactionNumber) ,MOV(6,@de25fda7@.ModbusMaster.Command[6].Output.TransactionNumber) ,MOV(7,@de25fda7@.ModbusMaster.Command[7].Output.TransactionNumber) ,MOV(8,@de25fda7@.ModbusMaster.Command[8].Output.TransactionNumber) ,MOV(9,@de25fda7@.ModbusMaster.Command[9].Output.TransactionNumber) ];
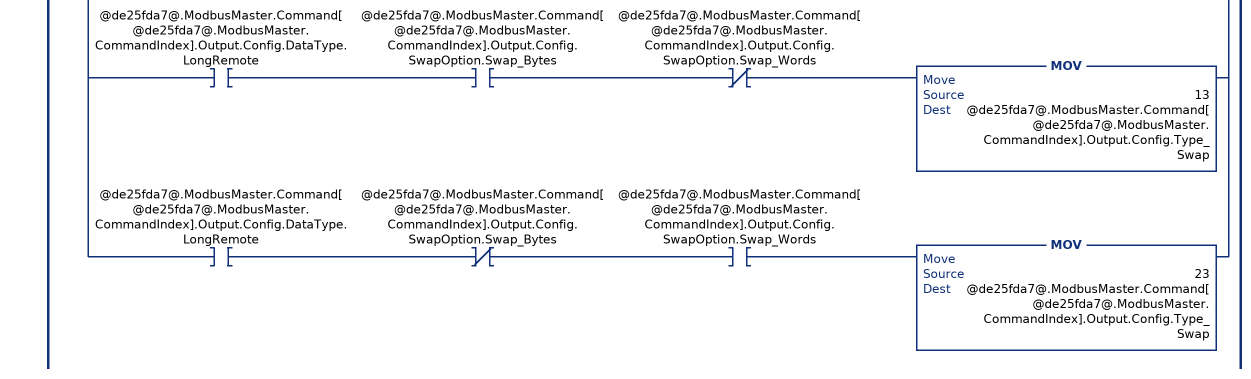
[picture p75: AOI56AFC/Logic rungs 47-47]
   // This handles the Modbus Master logic
   47: XIO(@de25fda7@.Flags.AFC_Set_Clock)[EQU(@de25fda7@.CycleCounter,1000) ,EQU(@de25fda7@.CycleCounter,1001) ]XIC(@de25fda7@.ModbusMaster.Enable)[[MOV(24576,@de25fda7@.ModbusMaster.Command[@de25fda7@.ModbusMaster.CommandIndex].Output.BOD) ,ADD(@de25fda7@.ModbusMaster.Command[@de25fda7@.ModbusMaster.CommandIndex].Output.BOD,130,@de25fda7@.ModbusMaster.Command[@de25fda7@.ModbusMaster.CommandIndex].Output.BOD) ] ,XIC(@de25fda7@.ModbusMaster.Command[@de25fda7@.ModbusMaster.CommandIndex].Output.Config.FunctionType_Write) OTE(@de25fda7@.ModbusMaster.Command[@de25fda7@.ModbusMaster.CommandIndex].Output.BOD.11) ,XIO(@de25fda7@.ModbusMaster.Command[@de25fda7@.ModbusMaster.CommandIndex].Output.Config.Enable) OTE(@de25fda7@.ModbusMaster.Command[@de25fda7@.ModbusMaster.CommandIndex].Output.BOD.8) ,XIC(@de25fda7@.ModbusMaster.Command[@de25fda7@.ModbusMaster.CommandIndex].Output.Config.RegisterBank_Input) OTE(@de25fda7@.ModbusMaster.Command[@de25fda7@.ModbusMaster.CommandIndex].Output.BOD.10) ,XIC(@de25fda7@.ModbusMaster.Command[@de25fda7@.ModbusMaster.CommandIndex].Output.Config.DataType.Bit) MOV(0,@de25fda7@.ModbusMaster.Command[@de25fda7@.ModbusMaster.CommandIndex].Output.Config.Type_Swap) ,XIC(@de25fda7@.ModbusMaster.Command[@de25fda7@.ModbusMaster.CommandIndex].Output.Config.DataType.Word) XIO(@de25fda7@.ModbusMaster.Command[@de25fda7@.ModbusMaster.CommandIndex].Output.Config.SwapOption.Swap_Bytes) MOV(1,@de25fda7@.ModbusMaster.Command[@de25fda7@.ModbusMaster.CommandIndex].Output.Config.Type_Swap) ,XIC(@de25fda7@.ModbusMaster.Command[@de25fda7@.ModbusMaster.CommandIndex].Output.Config.DataType.Word) XIC(@de25fda7@.ModbusMaster.Command[@de25fda7@.ModbusMaster.CommandIndex].Output.Config.SwapOption.Swap_Bytes) MOV(11,@de25fda7@.ModbusMaster.Command[@de25fda7@.ModbusMaster.CommandIndex].Output.Config.Type_Swap) ,XIC(@de25fda7@.ModbusMaster.Command[@de25fda7@.ModbusMaster.CommandIndex].Output.Config.DataType.Long) XIO(@de25fda7@.ModbusMaster.Command[@de25fda7@.ModbusMaster.CommandIndex].Output.Config.SwapOption.Swap_Bytes) XIO(@de25fda7@.ModbusMaster.Command[@de25fda7@.ModbusMaster.CommandIndex].Output.Config.SwapOption.Swap_Words) MOV(2,@de25fda7@.ModbusMaster.Command[@de25fda7@.ModbusMaster.CommandIndex].Output.Config.Type_Swap) ,XIC(@de25fda7@.ModbusMaster.Command[@de25fda7@.ModbusMaster.CommandIndex].Output.Config.DataType.Long) XIC(@de25fda7@.ModbusMaster.Command[@de25fda7@.ModbusMaster.CommandIndex].Output.Config.SwapOption.Swap_Bytes) XIO(@de25fda7@.ModbusMaster.Command[@de25fda7@.ModbusMaster.CommandIndex].Output.Config.SwapOption.Swap_Words) MOV(12,@de25fda7@.ModbusMaster.Command[@de25fda7@.ModbusMaster.CommandIndex].Output.Config.Type_Swap) ,XIC(@de25fda7@.ModbusMaster.Command[@de25fda7@.ModbusMaster.CommandIndex].Output.Config.DataType.Long) XIO(@de25fda7@.ModbusMaster.Command[@de25fda7@.ModbusMaster.CommandIndex].Output.Config.SwapOption.Swap_Bytes) XIC(@de25fda7@.ModbusMaster.Command[@de25fda7@.ModbusMaster.CommandIndex].Output.Config.SwapOption.Swap_Words) MOV(22,@de25fda7@.ModbusMaster.Command[@de25fda7@.ModbusMaster.CommandIndex].Output.Config.Type_Swap) ,XIC(@de25fda7@.ModbusMaster.Command[@de25fda7@.ModbusMaster.CommandIndex].Output.Config.DataType.LongRemote) XIO(@de25fda7@.ModbusMaster.Command[@de25fda7@.ModbusMaster.CommandIndex].Output.Config.SwapOption.Swap_Bytes) XIO(@de25fda7@.ModbusMaster.Command[@de25fda7@.ModbusMaster.CommandIndex].Output.Config.SwapOption.Swap_Words) MOV(3,@de25fda7@.ModbusMaster.Command[@de25fda7@.ModbusMaster.CommandIndex].Output.Config.Type_Swap) ,XIC(@de25fda7@.ModbusMaster.Command[@de25fda7@.ModbusMaster.CommandIndex].Output.Config.DataType.LongRemote) XIC(@de25fda7@.ModbusMaster.Command[@de25fda7@.ModbusMaster.CommandIndex].Output.Config.SwapOption.Swap_Bytes) XIO(@de25fda7@.ModbusMaster.Command[@de25fda7@.ModbusMaster.CommandIndex].Output.Config.SwapOption.Swap_Words) MOV(13,@de25fda7@.ModbusMaster.Command[@de25fda7@.ModbusMaster.CommandIndex].Output.Config.Type_Swap) ,XIC(@de25fda7@.ModbusMaster.Command[@de25fda7@.ModbusMaster.CommandIndex].Output.Config.DataType.LongRemote) XIO(@de25fda7@.ModbusMaster.Command[@de25fda7@.ModbusMaster.CommandIndex].Output.Config.SwapOption.Swap_Bytes) XIC(@de25fda7@.ModbusMaster.Command[@de25fda7@.ModbusMaster.CommandIndex].Output.Config.SwapOption.Swap_Words) MOV(23,@de25fda7@.ModbusMaster.Command[@de25fda7@.ModbusMaster.CommandIndex].Output.Config.Type_Swap) ];
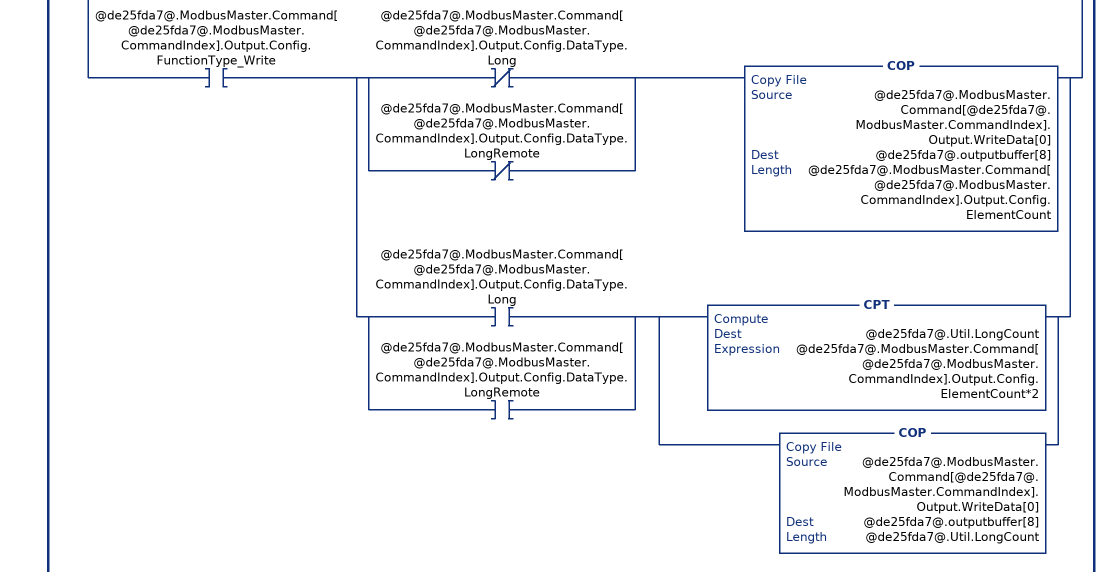
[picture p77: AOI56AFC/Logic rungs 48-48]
   48: XIO(@de25fda7@.Flags.AFC_Set_Clock)[EQU(@de25fda7@.CycleCounter,1000) ,EQU(@de25fda7@.CycleCounter,1001) ]XIC(@de25fda7@.ModbusMaster.Enable)[MOV(131,@de25fda7@.outputbuffer[1]) ,MOV(@de25fda7@.ModbusMaster.Command[@de25fda7@.ModbusMaster.CommandIndex].Output.BOD,@de25fda7@.outputbuffer[2]) ,MOV(@de25fda7@.ModbusMaster.Command[@de25fda7@.ModbusMaster.CommandIndex].Output.TransactionNumber,@de25fda7@.outputbuffer[3]) ,MOV(@de25fda7@.ModbusMaster.Command[@de25fda7@.ModbusMaster.CommandIndex].Output.Config.Type_Swap,@de25fda7@.outputbuffer[4]) ,MOV(@de25fda7@.ModbusMaster.Command[@de25fda7@.ModbusMaster.CommandIndex].Output.Config.SlaveAddress,@de25fda7@.outputbuffer[5]) ,MOV(@de25fda7@.ModbusMaster.Command[@de25fda7@.ModbusMaster.CommandIndex].Output.Config.ModbusAddress,@de25fda7@.outputbuffer[6]) ,MOV(@de25fda7@.ModbusMaster.Command[@de25fda7@.ModbusMaster.CommandIndex].Output.Config.ElementCount,@de25fda7@.outputbuffer[7]) ,XIC(@de25fda7@.ModbusMaster.Command[@de25fda7@.ModbusMaster.CommandIndex].Output.Config.FunctionType_Write) [[XIO(@de25fda7@.ModbusMaster.Command[@de25fda7@.ModbusMaster.CommandIndex].Output.Config.DataType.Long) ,XIO(@de25fda7@.ModbusMaster.Command[@de25fda7@.ModbusMaster.CommandIndex].Output.Config.DataType.LongRemote) ] COP(@de25fda7@.ModbusMaster.Command[@de25fda7@.ModbusMaster.CommandIndex].Output.WriteData[0],@de25fda7@.outputbuffer[8],@de25fda7@.ModbusMaster.Command[@de25fda7@.ModbusMaster.CommandIndex].Output.Config.ElementCount) ,[XIC(@de25fda7@.ModbusMaster.Command[@de25fda7@.ModbusMaster.CommandIndex].Output.Config.DataType.Long) ,XIC(@de25fda7@.ModbusMaster.Command[@de25fda7@.ModbusMaster.CommandIndex].Output.Config.DataType.LongRemote) ] [CPT(@de25fda7@.Util.LongCount,@de25fda7@.ModbusMaster.Command[@de25fda7@.ModbusMaster.CommandIndex].Output.Config.ElementCount*2) ,COP(@de25fda7@.ModbusMaster.Command[@de25fda7@.ModbusMaster.CommandIndex].Output.WriteData[0],@de25fda7@.outputbuffer[8],@de25fda7@.Util.LongCount) ] ] ];
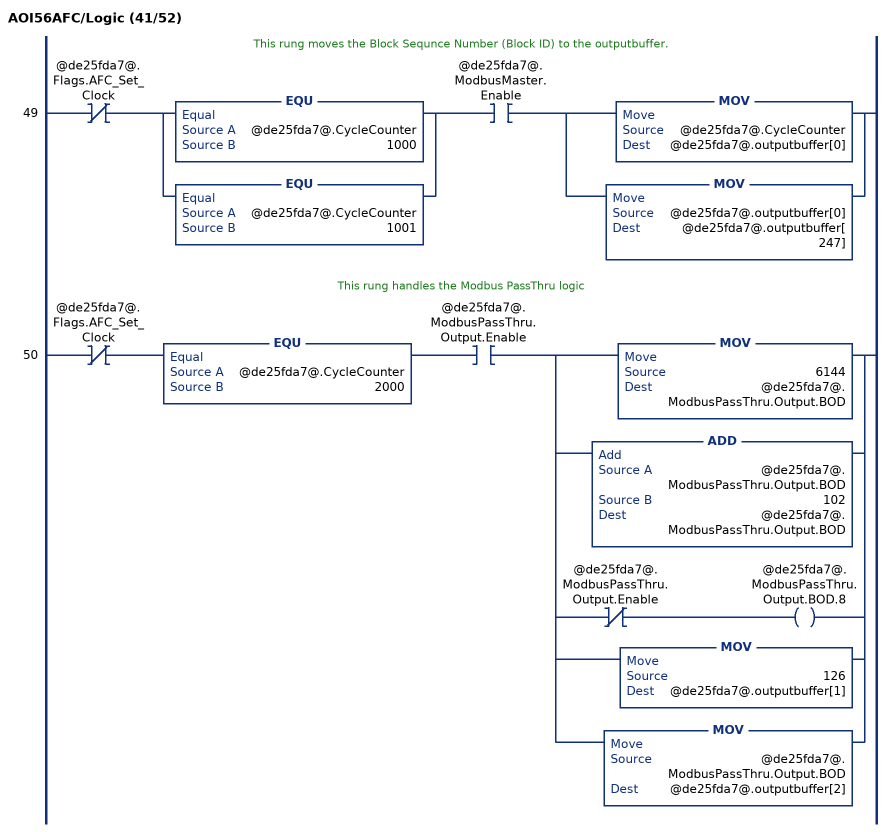
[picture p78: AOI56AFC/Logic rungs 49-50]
   // This rung moves the Block Sequnce Number (Block ID) to the outputbuffer.
   49: XIO(@de25fda7@.Flags.AFC_Set_Clock)[EQU(@de25fda7@.CycleCounter,1000) ,EQU(@de25fda7@.CycleCounter,1001) ]XIC(@de25fda7@.ModbusMaster.Enable)[MOV(@de25fda7@.CycleCounter,@de25fda7@.outputbuffer[0]) ,MOV(@de25fda7@.outputbuffer[0],@de25fda7@.outputbuffer[247]) ];
   // This rung handles the Modbus PassThru logic
   50: XIO(@de25fda7@.Flags.AFC_Set_Clock)EQU(@de25fda7@.CycleCounter,2000)XIC(@de25fda7@.ModbusPassThru.Output.Enable)[MOV(6144,@de25fda7@.ModbusPassThru.Output.BOD) ,ADD(@de25fda7@.ModbusPassThru.Output.BOD,102,@de25fda7@.ModbusPassThru.Output.BOD) ,XIO(@de25fda7@.ModbusPassThru.Output.Enable) OTE(@de25fda7@.ModbusPassThru.Output.BOD.8) ,MOV(126,@de25fda7@.outputbuffer[1]) ,MOV(@de25fda7@.ModbusPassThru.Output.BOD,@de25fda7@.outputbuffer[2]) ];
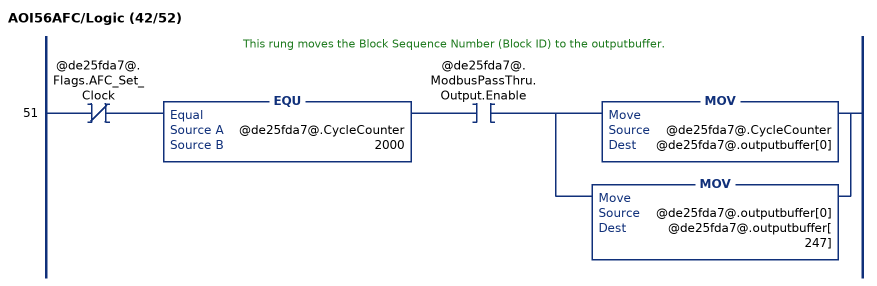
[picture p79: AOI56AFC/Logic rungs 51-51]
   // This rung moves the Block Sequence Number (Block ID) to the outputbuffer.
   51: XIO(@de25fda7@.Flags.AFC_Set_Clock)EQU(@de25fda7@.CycleCounter,2000)XIC(@de25fda7@.ModbusPassThru.Output.Enable)[MOV(@de25fda7@.CycleCounter,@de25fda7@.outputbuffer[0]) ,MOV(@de25fda7@.outputbuffer[0],@de25fda7@.outputbuffer[247]) ];
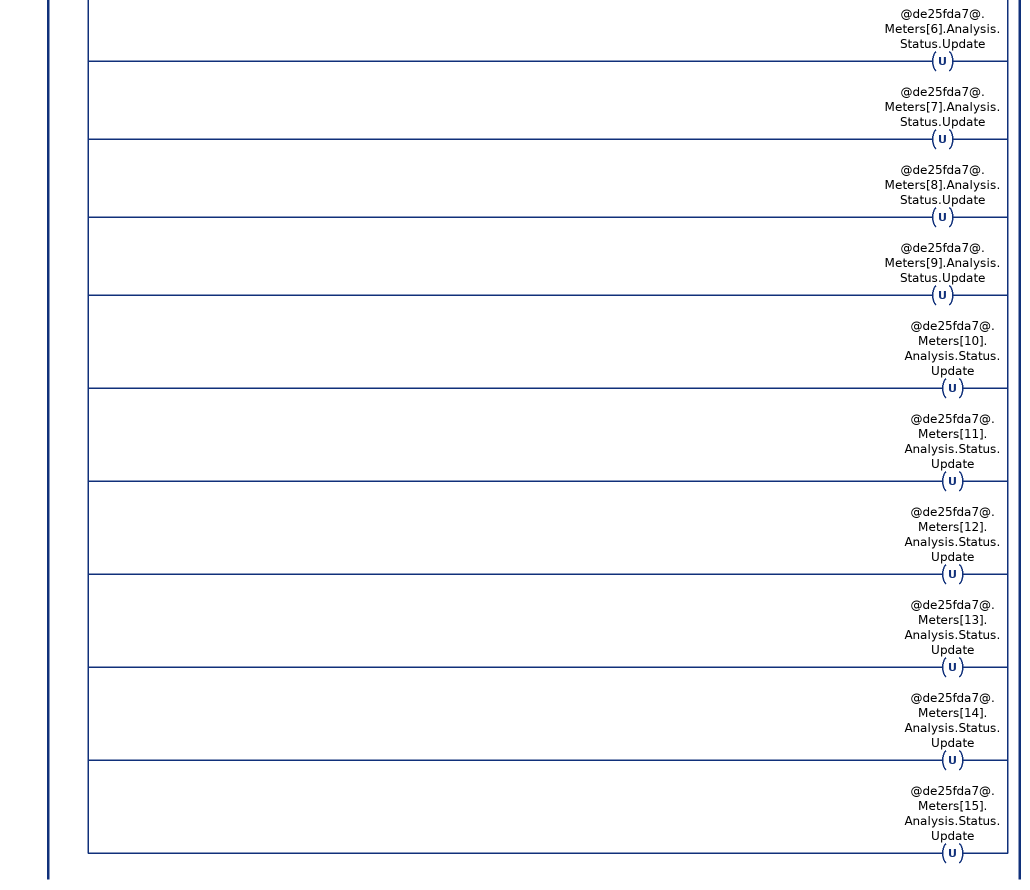
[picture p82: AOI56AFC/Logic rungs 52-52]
   52: XIO(@de25fda7@.Flags.AFC_Set_Clock)XIC(@de25fda7@.inputbuffer[247].11)LIM(3000,@de25fda7@.CycleCounter,3009)EQU(@de25fda7@.CycleCounter,3000)[XIC(@de25fda7@.Meters[0].Analysis.Status.Update) ,XIC(@de25fda7@.Meters[1].Analysis.Status.Update) ,XIC(@de25fda7@.Meters[2].Analysis.Status.Update) ,XIC(@de25fda7@.Meters[3].Analysis.Status.Update) ,XIC(@de25fda7@.Meters[4].Analysis.Status.Update) ,XIC(@de25fda7@.Meters[5].Analysis.Status.Update) ,XIC(@de25fda7@.Meters[6].Analysis.Status.Update) ,XIC(@de25fda7@.Meters[7].Analysis.Status.Update) ,XIC(@de25fda7@.Meters[8].Analysis.Status.Update) ,XIC(@de25fda7@.Meters[9].Analysis.Status.Update) ,XIC(@de25fda7@.Meters[10].Analysis.Status.Update) ,XIC(@de25fda7@.Meters[11].Analysis.Status.Update) ,XIC(@de25fda7@.Meters[12].Analysis.Status.Update) ,XIC(@de25fda7@.Meters[13].Analysis.Status.Update) ,XIC(@de25fda7@.Meters[14].Analysis.Status.Update) ,XIC(@de25fda7@.Meters[15].Analysis.Status.Update) ][MOV(11553,@de25fda7@.Util.AnalysisHighPrecisionBID_Update) ,MOV(49,@de25fda7@.outputbuffer[1]) ,MOV(@de25fda7@.Util.AnalysisHighPrecisionBID_Update,@de25fda7@.outputbuffer[2]) ,OTU(@de25fda7@.Meters[0].Analysis.Status.Update) ,OTU(@de25fda7@.Meters[1].Analysis.Status.Update) ,OTU(@de25fda7@.Meters[2].Analysis.Status.Update) ,OTU(@de25fda7@.Meters[3].Analysis.Status.Update) ,OTU(@de25fda7@.Meters[4].Analysis.Status.Update) ,OTU(@de25fda7@.Meters[5].Analysis.Status.Update) ,OTU(@de25fda7@.Meters[6].Analysis.Status.Update) ,OTU(@de25fda7@.Meters[7].Analysis.Status.Update) ,OTU(@de25fda7@.Meters[8].Analysis.Status.Update) ,OTU(@de25fda7@.Meters[9].Analysis.Status.Update) ,OTU(@de25fda7@.Meters[10].Analysis.Status.Update) ,OTU(@de25fda7@.Meters[11].Analysis.Status.Update) ,OTU(@de25fda7@.Meters[12].Analysis.Status.Update) ,OTU(@de25fda7@.Meters[13].Analysis.Status.Update) ,OTU(@de25fda7@.Meters[14].Analysis.Status.Update) ,OTU(@de25fda7@.Meters[15].Analysis.Status.Update) ];
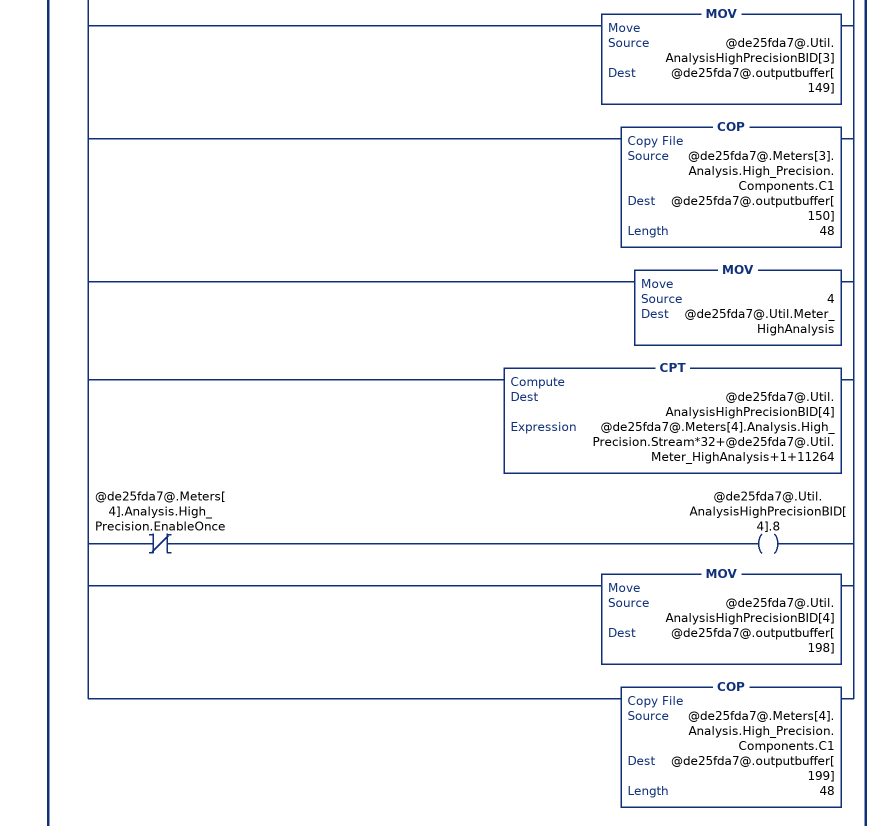
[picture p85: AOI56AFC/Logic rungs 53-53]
   53: XIO(@de25fda7@.Flags.AFC_Set_Clock)XIC(@de25fda7@.inputbuffer[247].11)LIM(3000,@de25fda7@.CycleCounter,3009)EQU(@de25fda7@.CycleCounter,3001)[MOV(245,@de25fda7@.outputbuffer[1]) ,MOV(0,@de25fda7@.Util.Meter_HighAnalysis) ,CPT(@de25fda7@.Util.AnalysisHighPrecisionBID[0],@de25fda7@.Meters[0].Analysis.High_Precision.Stream*32+@de25fda7@.Util.Meter_HighAnalysis+1+11264) ,XIO(@de25fda7@.Meters[0].Analysis.High_Precision.EnableOnce) OTE(@de25fda7@.Util.AnalysisHighPrecisionBID[0].8) ,MOV(@de25fda7@.Util.AnalysisHighPrecisionBID[0],@de25fda7@.outputbuffer[2]) ,COP(@de25fda7@.Meters[0].Analysis.High_Precision.Components.C1,@de25fda7@.outputbuffer[3],48) ,MOV(1,@de25fda7@.Util.Meter_HighAnalysis) ,CPT(@de25fda7@.Util.AnalysisHighPrecisionBID[1],@de25fda7@.Meters[1].Analysis.High_Precision.Stream*32+@de25fda7@.Util.Meter_HighAnalysis+1+11264) ,XIO(@de25fda7@.Meters[1].Analysis.High_Precision.EnableOnce) OTE(@de25fda7@.Util.AnalysisHighPrecisionBID[1].8) ,MOV(@de25fda7@.Util.AnalysisHighPrecisionBID[1],@de25fda7@.outputbuffer[51]) ,COP(@de25fda7@.Meters[1].Analysis.High_Precision.Components.C1,@de25fda7@.outputbuffer[52],48) ,MOV(2,@de25fda7@.Util.Meter_HighAnalysis) ,CPT(@de25fda7@.Util.AnalysisHighPrecisionBID[2],@de25fda7@.Meters[2].Analysis.High_Precision.Stream*32+@de25fda7@.Util.Meter_HighAnalysis+1+11264) ,XIO(@de25fda7@.Meters[2].Analysis.High_Precision.EnableOnce) OTE(@de25fda7@.Util.AnalysisHighPrecisionBID[2].8) ,MOV(@de25fda7@.Util.AnalysisHighPrecisionBID[2],@de25fda7@.outputbuffer[100]) ,COP(@de25fda7@.Meters[2].Analysis.High_Precision.Components.C1,@de25fda7@.outputbuffer[101],48) ,MOV(3,@de25fda7@.Util.Meter_HighAnalysis) ,CPT(@de25fda7@.Util.AnalysisHighPrecisionBID[3],@de25fda7@.Meters[3].Analysis.High_Precision.Stream*32+@de25fda7@.Util.Meter_HighAnalysis+1+11264) ,XIO(@de25fda7@.Meters[3].Analysis.High_Precision.EnableOnce) OTE(@de25fda7@.Util.AnalysisHighPrecisionBID[3].8) ,MOV(@de25fda7@.Util.AnalysisHighPrecisionBID[3],@de25fda7@.outputbuffer[149]) ,COP(@de25fda7@.Meters[3].Analysis.High_Precision.Components.C1,@de25fda7@.outputbuffer[150],48) ,MOV(4,@de25fda7@.Util.Meter_HighAnalysis) ,CPT(@de25fda7@.Util.AnalysisHighPrecisionBID[4],@de25fda7@.Meters[4].Analysis.High_Precision.Stream*32+@de25fda7@.Util.Meter_HighAnalysis+1+11264) ,XIO(@de25fda7@.Meters[4].Analysis.High_Precision.EnableOnce) OTE(@de25fda7@.Util.AnalysisHighPrecisionBID[4].8) ,MOV(@de25fda7@.Util.AnalysisHighPrecisionBID[4],@de25fda7@.outputbuffer[198]) ,COP(@de25fda7@.Meters[4].Analysis.High_Precision.Components.C1,@de25fda7@.outputbuffer[199],48) ];
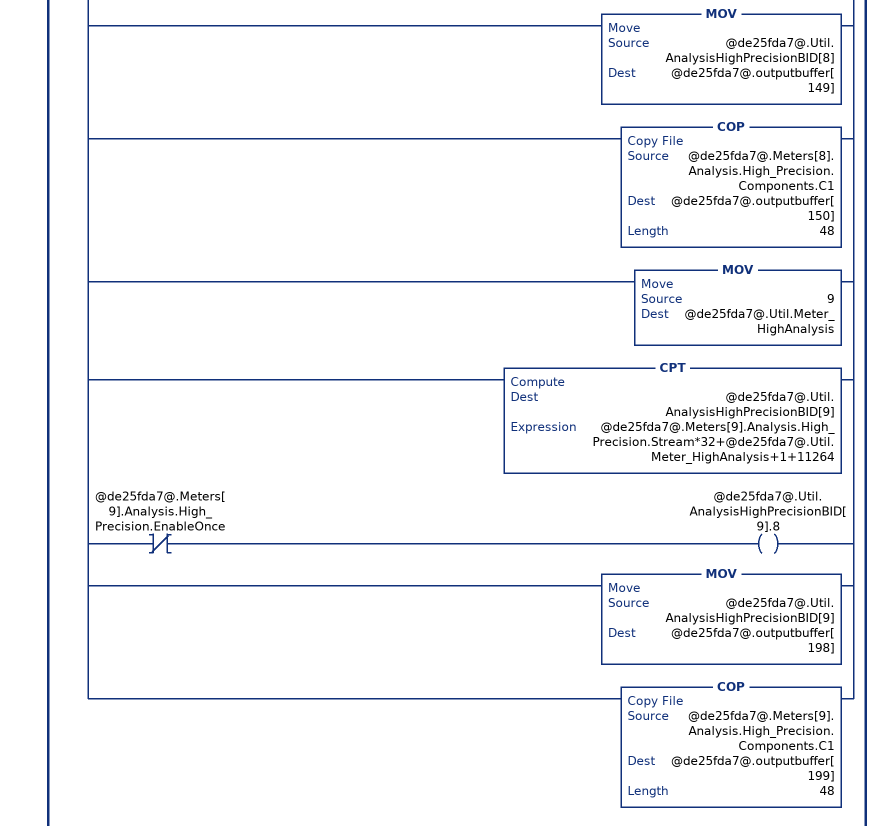
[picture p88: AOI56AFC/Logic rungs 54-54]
   54: XIO(@de25fda7@.Flags.AFC_Set_Clock)XIC(@de25fda7@.inputbuffer[247].11)LIM(3000,@de25fda7@.CycleCounter,3009)EQU(@de25fda7@.CycleCounter,3002)[MOV(245,@de25fda7@.outputbuffer[1]) ,MOV(5,@de25fda7@.Util.Meter_HighAnalysis) ,CPT(@de25fda7@.Util.AnalysisHighPrecisionBID[5],@de25fda7@.Meters[5].Analysis.High_Precision.Stream*32+@de25fda7@.Util.Meter_HighAnalysis+1+11264) ,XIO(@de25fda7@.Meters[5].Analysis.High_Precision.EnableOnce) OTE(@de25fda7@.Util.AnalysisHighPrecisionBID[5].8) ,MOV(@de25fda7@.Util.AnalysisHighPrecisionBID[5],@de25fda7@.outputbuffer[2]) ,COP(@de25fda7@.Meters[5].Analysis.High_Precision.Components.C1,@de25fda7@.outputbuffer[3],48) ,MOV(6,@de25fda7@.Util.Meter_HighAnalysis) ,CPT(@de25fda7@.Util.AnalysisHighPrecisionBID[6],@de25fda7@.Meters[6].Analysis.High_Precision.Stream*32+@de25fda7@.Util.Meter_HighAnalysis+1+11264) ,XIO(@de25fda7@.Meters[6].Analysis.High_Precision.EnableOnce) OTE(@de25fda7@.Util.AnalysisHighPrecisionBID[6].8) ,MOV(@de25fda7@.Util.AnalysisHighPrecisionBID[6],@de25fda7@.outputbuffer[51]) ,COP(@de25fda7@.Meters[6].Analysis.High_Precision.Components.C1,@de25fda7@.outputbuffer[52],48) ,MOV(7,@de25fda7@.Util.Meter_HighAnalysis) ,CPT(@de25fda7@.Util.AnalysisHighPrecisionBID[7],@de25fda7@.Meters[7].Analysis.High_Precision.Stream*32+@de25fda7@.Util.Meter_HighAnalysis+1+11264) ,XIO(@de25fda7@.Meters[7].Analysis.High_Precision.EnableOnce) OTE(@de25fda7@.Util.AnalysisHighPrecisionBID[7].8) ,MOV(@de25fda7@.Util.AnalysisHighPrecisionBID[7],@de25fda7@.outputbuffer[100]) ,COP(@de25fda7@.Meters[7].Analysis.High_Precision.Components.C1,@de25fda7@.outputbuffer[101],48) ,MOV(8,@de25fda7@.Util.Meter_HighAnalysis) ,CPT(@de25fda7@.Util.AnalysisHighPrecisionBID[8],@de25fda7@.Meters[8].Analysis.High_Precision.Stream*32+@de25fda7@.Util.Meter_HighAnalysis+1+11264) ,XIO(@de25fda7@.Meters[8].Analysis.High_Precision.EnableOnce) OTE(@de25fda7@.Util.AnalysisHighPrecisionBID[8].8) ,MOV(@de25fda7@.Util.AnalysisHighPrecisionBID[8],@de25fda7@.outputbuffer[149]) ,COP(@de25fda7@.Meters[8].Analysis.High_Precision.Components.C1,@de25fda7@.outputbuffer[150],48) ,MOV(9,@de25fda7@.Util.Meter_HighAnalysis) ,CPT(@de25fda7@.Util.AnalysisHighPrecisionBID[9],@de25fda7@.Meters[9].Analysis.High_Precision.Stream*32+@de25fda7@.Util.Meter_HighAnalysis+1+11264) ,XIO(@de25fda7@.Meters[9].Analysis.High_Precision.EnableOnce) OTE(@de25fda7@.Util.AnalysisHighPrecisionBID[9].8) ,MOV(@de25fda7@.Util.AnalysisHighPrecisionBID[9],@de25fda7@.outputbuffer[198]) ,COP(@de25fda7@.Meters[9].Analysis.High_Precision.Components.C1,@de25fda7@.outputbuffer[199],48) ];
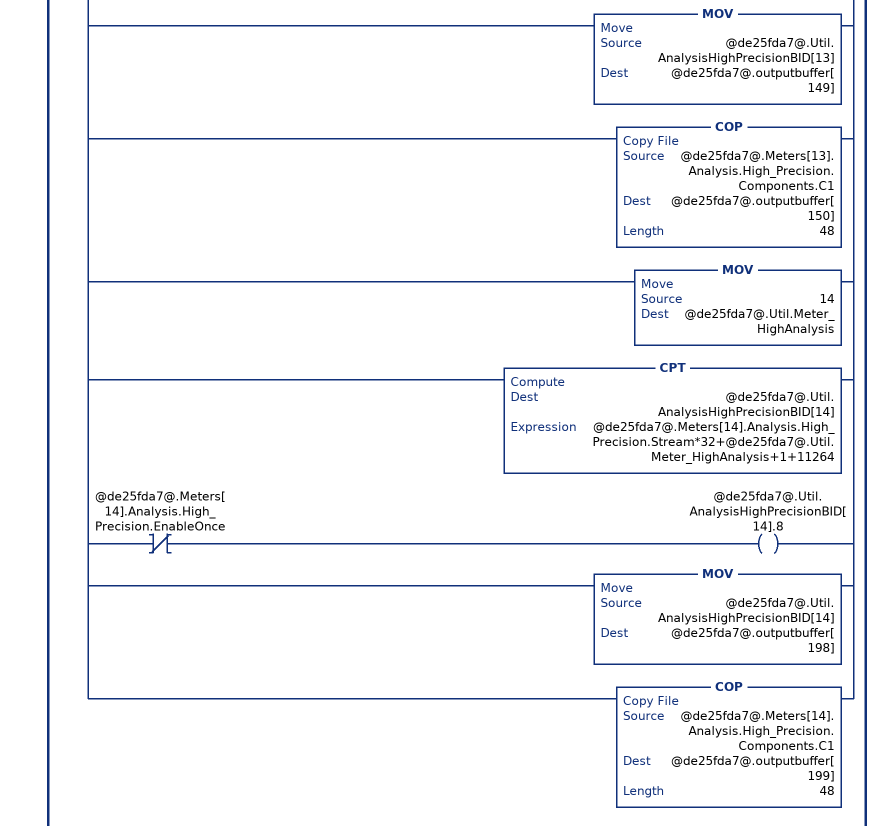
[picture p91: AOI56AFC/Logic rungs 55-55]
   55: XIO(@de25fda7@.Flags.AFC_Set_Clock)XIC(@de25fda7@.inputbuffer[247].11)LIM(3000,@de25fda7@.CycleCounter,3009)EQU(@de25fda7@.CycleCounter,3003)[MOV(245,@de25fda7@.outputbuffer[1]) ,MOV(10,@de25fda7@.Util.Meter_HighAnalysis) ,CPT(@de25fda7@.Util.AnalysisHighPrecisionBID[10],@de25fda7@.Meters[10].Analysis.High_Precision.Stream*32+@de25fda7@.Util.Meter_HighAnalysis+1+11264) ,XIO(@de25fda7@.Meters[10].Analysis.High_Precision.EnableOnce) OTE(@de25fda7@.Util.AnalysisHighPrecisionBID[10].8) ,MOV(@de25fda7@.Util.AnalysisHighPrecisionBID[10],@de25fda7@.outputbuffer[2]) ,COP(@de25fda7@.Meters[10].Analysis.High_Precision.Components.C1,@de25fda7@.outputbuffer[3],48) ,MOV(11,@de25fda7@.Util.Meter_HighAnalysis) ,CPT(@de25fda7@.Util.AnalysisHighPrecisionBID[11],@de25fda7@.Meters[11].Analysis.High_Precision.Stream*32+@de25fda7@.Util.Meter_HighAnalysis+1+11264) ,XIO(@de25fda7@.Meters[11].Analysis.High_Precision.EnableOnce) OTE(@de25fda7@.Util.AnalysisHighPrecisionBID[11].8) ,MOV(@de25fda7@.Util.AnalysisHighPrecisionBID[11],@de25fda7@.outputbuffer[51]) ,COP(@de25fda7@.Meters[11].Analysis.High_Precision.Components.C1,@de25fda7@.outputbuffer[52],48) ,MOV(12,@de25fda7@.Util.Meter_HighAnalysis) ,CPT(@de25fda7@.Util.AnalysisHighPrecisionBID[12],@de25fda7@.Meters[12].Analysis.High_Precision.Stream*32+@de25fda7@.Util.Meter_HighAnalysis+1+11264) ,XIO(@de25fda7@.Meters[12].Analysis.High_Precision.EnableOnce) OTE(@de25fda7@.Util.AnalysisHighPrecisionBID[12].8) ,MOV(@de25fda7@.Util.AnalysisHighPrecisionBID[12],@de25fda7@.outputbuffer[100]) ,COP(@de25fda7@.Meters[12].Analysis.High_Precision.Components.C1,@de25fda7@.outputbuffer[101],48) ,MOV(13,@de25fda7@.Util.Meter_HighAnalysis) ,CPT(@de25fda7@.Util.AnalysisHighPrecisionBID[13],@de25fda7@.Meters[13].Analysis.High_Precision.Stream*32+@de25fda7@.Util.Meter_HighAnalysis+1+11264) ,XIO(@de25fda7@.Meters[13].Analysis.High_Precision.EnableOnce) OTE(@de25fda7@.Util.AnalysisHighPrecisionBID[13].8) ,MOV(@de25fda7@.Util.AnalysisHighPrecisionBID[13],@de25fda7@.outputbuffer[149]) ,COP(@de25fda7@.Meters[13].Analysis.High_Precision.Components.C1,@de25fda7@.outputbuffer[150],48) ,MOV(14,@de25fda7@.Util.Meter_HighAnalysis) ,CPT(@de25fda7@.Util.AnalysisHighPrecisionBID[14],@de25fda7@.Meters[14].Analysis.High_Precision.Stream*32+@de25fda7@.Util.Meter_HighAnalysis+1+11264) ,XIO(@de25fda7@.Meters[14].Analysis.High_Precision.EnableOnce) OTE(@de25fda7@.Util.AnalysisHighPrecisionBID[14].8) ,MOV(@de25fda7@.Util.AnalysisHighPrecisionBID[14],@de25fda7@.outputbuffer[198]) ,COP(@de25fda7@.Meters[14].Analysis.High_Precision.Components.C1,@de25fda7@.outputbuffer[199],48) ];
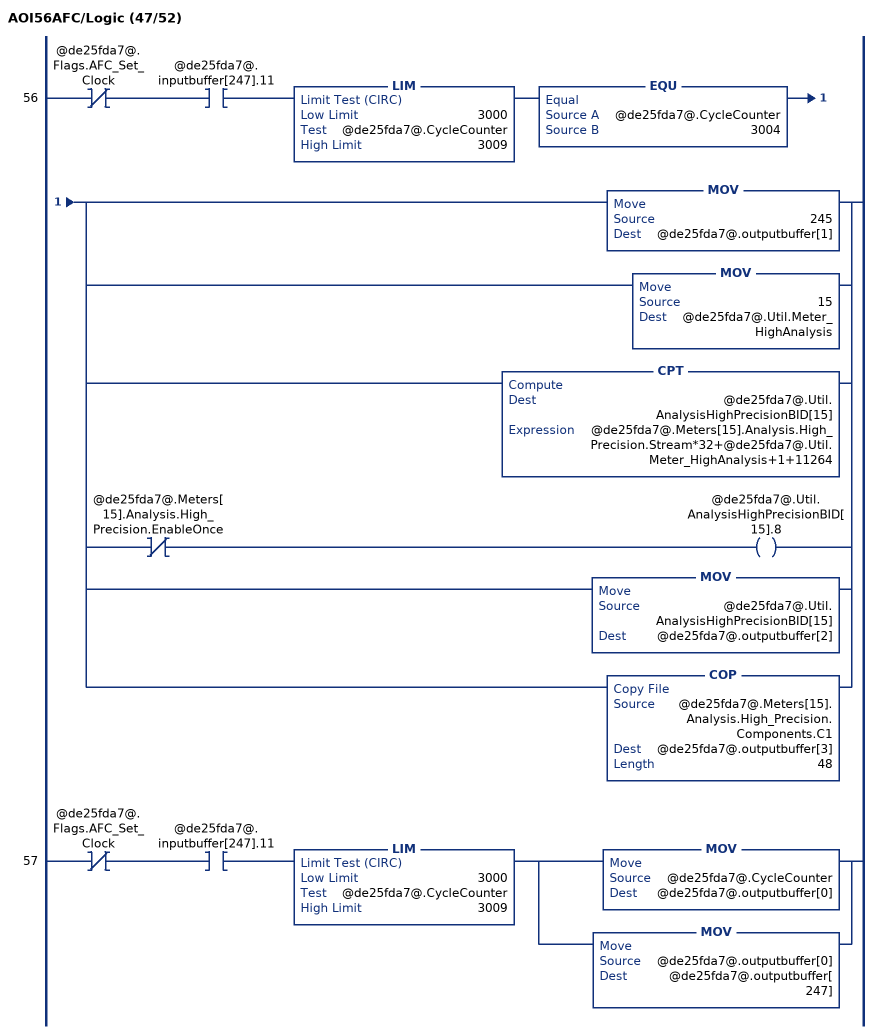
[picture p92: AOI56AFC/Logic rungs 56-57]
   56: XIO(@de25fda7@.Flags.AFC_Set_Clock)XIC(@de25fda7@.inputbuffer[247].11)LIM(3000,@de25fda7@.CycleCounter,3009)EQU(@de25fda7@.CycleCounter,3004)[MOV(245,@de25fda7@.outputbuffer[1]) ,MOV(15,@de25fda7@.Util.Meter_HighAnalysis) ,CPT(@de25fda7@.Util.AnalysisHighPrecisionBID[15],@de25fda7@.Meters[15].Analysis.High_Precision.Stream*32+@de25fda7@.Util.Meter_HighAnalysis+1+11264) ,XIO(@de25fda7@.Meters[15].Analysis.High_Precision.EnableOnce) OTE(@de25fda7@.Util.AnalysisHighPrecisionBID[15].8) ,MOV(@de25fda7@.Util.AnalysisHighPrecisionBID[15],@de25fda7@.outputbuffer[2]) ,COP(@de25fda7@.Meters[15].Analysis.High_Precision.Components.C1,@de25fda7@.outputbuffer[3],48) ];
   57: XIO(@de25fda7@.Flags.AFC_Set_Clock)XIC(@de25fda7@.inputbuffer[247].11)LIM(3000,@de25fda7@.CycleCounter,3009)[MOV(@de25fda7@.CycleCounter,@de25fda7@.outputbuffer[0]) ,MOV(@de25fda7@.outputbuffer[0],@de25fda7@.outputbuffer[247]) ];
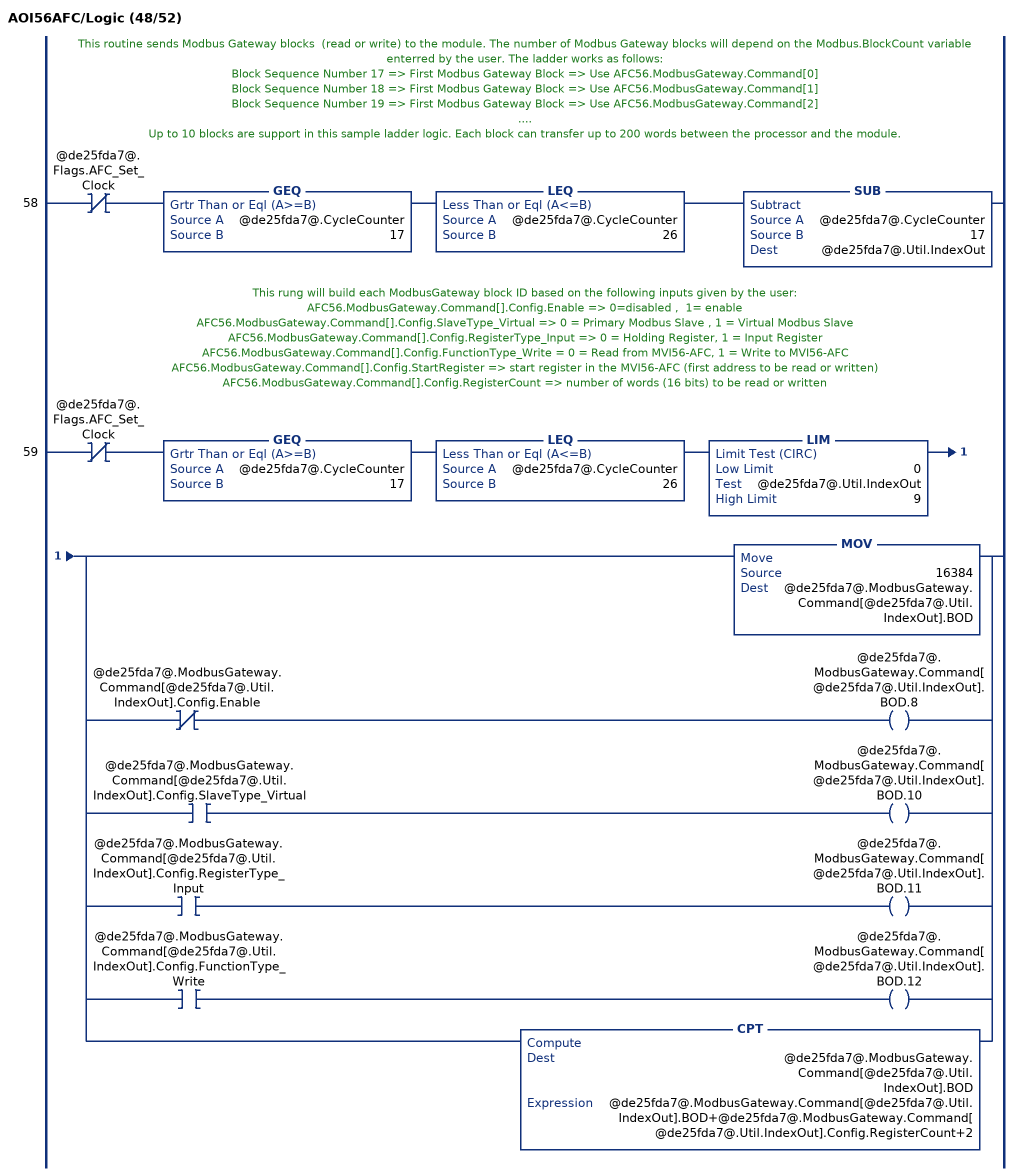
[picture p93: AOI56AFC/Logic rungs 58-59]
   // This routine sends Modbus Gateway blocks  (read or write) to the module. The number of Modbus Gateway blocks will depend on the Modbus.BlockCount variable enterred by the user. The ladder works as follows:
   // Block Sequence Number 17 => First Modbus Gateway Block => Use AFC56.ModbusGateway.Command[0]
   // Block Sequence Number 18 => First Modbus Gateway Block => Use AFC56.ModbusGateway.Command[1]
   // Block Sequence Number 19 => First Modbus Gateway Block => Use AFC56.ModbusGateway.Command[2]
   // ....
   // Up to 10 blocks are support in this sample ladder logic. Each block can transfer up to 200 words between the processor and the module.
   58: XIO(@de25fda7@.Flags.AFC_Set_Clock)GEQ(@de25fda7@.CycleCounter,17)LEQ(@de25fda7@.CycleCounter,26)SUB(@de25fda7@.CycleCounter,17,@de25fda7@.Util.IndexOut);
   // This rung will build each ModbusGateway block ID based on the following inputs given by the user:
   // AFC56.ModbusGateway.Command[].Config.Enable => 0=disabled ,  1= enable
   // AFC56.ModbusGateway.Command[].Config.SlaveType_Virtual => 0 = Primary Modbus Slave , 1 = Virtual Modbus Slave
   // AFC56.ModbusGateway.Command[].Config.RegisterType_Input => 0 = Holding Register, 1 = Input Register
   // AFC56.ModbusGateway.Command[].Config.FunctionType_Write = 0 = Read from MVI56-AFC, 1 = Write to MVI56-AFC
   // AFC56.ModbusGateway.Command[].Config.StartRegister => start register in the MVI56-AFC (first address to be read or written)
   // AFC56.ModbusGateway.Command[].Config.RegisterCount => number of words (16 bits) to be read or written
   59: XIO(@de25fda7@.Flags.AFC_Set_Clock)GEQ(@de25fda7@.CycleCounter,17)LEQ(@de25fda7@.CycleCounter,26)LIM(0,@de25fda7@.Util.IndexOut,9)[MOV(16384,@de25fda7@.ModbusGateway.Command[@de25fda7@.Util.IndexOut].BOD) ,XIO(@de25fda7@.ModbusGateway.Command[@de25fda7@.Util.IndexOut].Config.Enable) OTE(@de25fda7@.ModbusGateway.Command[@de25fda7@.Util.IndexOut].BOD.8) ,XIC(@de25fda7@.ModbusGateway.Command[@de25fda7@.Util.IndexOut].Config.SlaveType_Virtual) OTE(@de25fda7@.ModbusGateway.Command[@de25fda7@.Util.IndexOut].BOD.10) ,XIC(@de25fda7@.ModbusGateway.Command[@de25fda7@.Util.IndexOut].Config.RegisterType_Input) OTE(@de25fda7@.ModbusGateway.Command[@de25fda7@.Util.IndexOut].BOD.11) ,XIC(@de25fda7@.ModbusGateway.Command[@de25fda7@.Util.IndexOut].Config.FunctionType_Write) OTE(@de25fda7@.ModbusGateway.Command[@de25fda7@.Util.IndexOut].BOD.12) ,CPT(@de25fda7@.ModbusGateway.Command[@de25fda7@.Util.IndexOut].BOD,@de25fda7@.ModbusGateway.Command[@de25fda7@.Util.IndexOut].BOD+@de25fda7@.ModbusGateway.Command[@de25fda7@.Util.IndexOut].Config.RegisterCount+2) ];
(* Logix 5000 Rung export; software revision 16.03; part 3 of 3 *)
(* AOI56AFC, continued *)

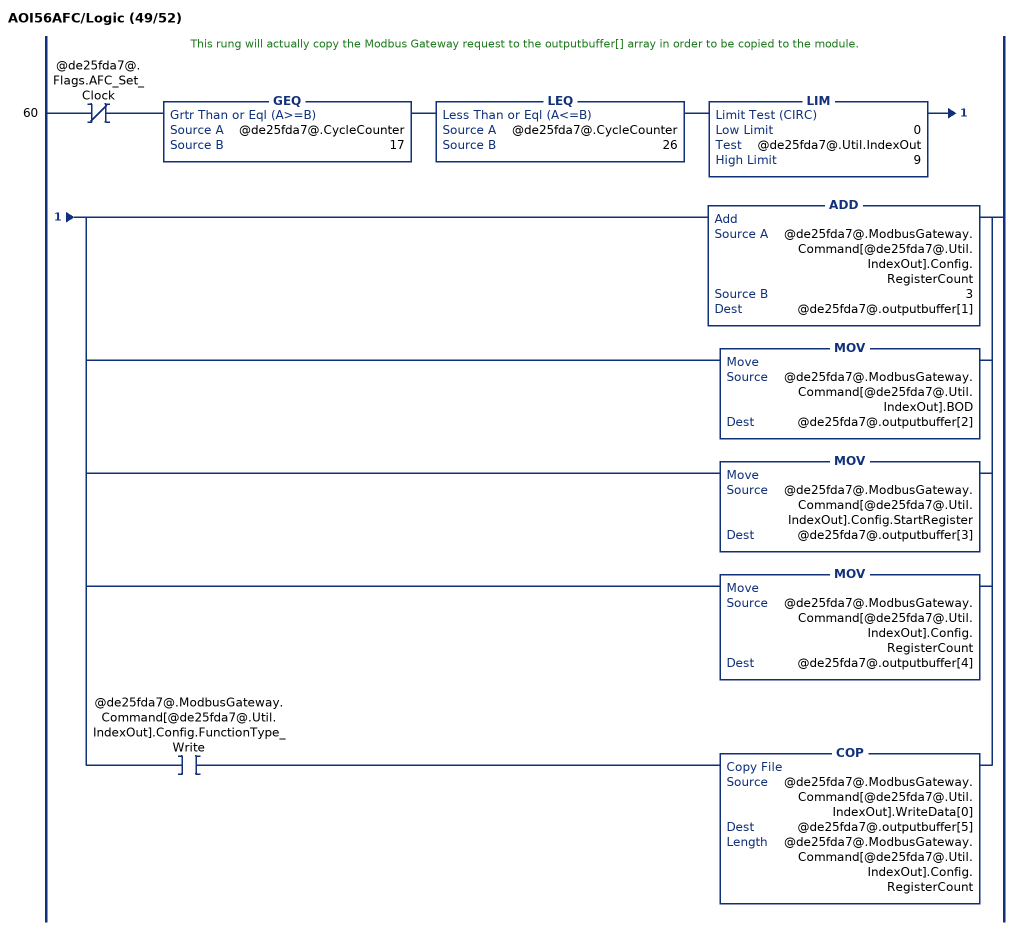
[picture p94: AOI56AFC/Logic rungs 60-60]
   // This rung will actually copy the Modbus Gateway request to the outputbuffer[] array in order to be copied to the module.
   60: XIO(@de25fda7@.Flags.AFC_Set_Clock)GEQ(@de25fda7@.CycleCounter,17)LEQ(@de25fda7@.CycleCounter,26)LIM(0,@de25fda7@.Util.IndexOut,9)[ADD(@de25fda7@.ModbusGateway.Command[@de25fda7@.Util.IndexOut].Config.RegisterCount,3,@de25fda7@.outputbuffer[1]) ,MOV(@de25fda7@.ModbusGateway.Command[@de25fda7@.Util.IndexOut].BOD,@de25fda7@.outputbuffer[2]) ,MOV(@de25fda7@.ModbusGateway.Command[@de25fda7@.Util.IndexOut].Config.StartRegister,@de25fda7@.outputbuffer[3]) ,MOV(@de25fda7@.ModbusGateway.Command[@de25fda7@.Util.IndexOut].Config.RegisterCount,@de25fda7@.outputbuffer[4]) ,XIC(@de25fda7@.ModbusGateway.Command[@de25fda7@.Util.IndexOut].Config.FunctionType_Write) COP(@de25fda7@.ModbusGateway.Command[@de25fda7@.Util.IndexOut].WriteData[0],@de25fda7@.outputbuffer[5],@de25fda7@.ModbusGateway.Command[@de25fda7@.Util.IndexOut].Config.RegisterCount) ];
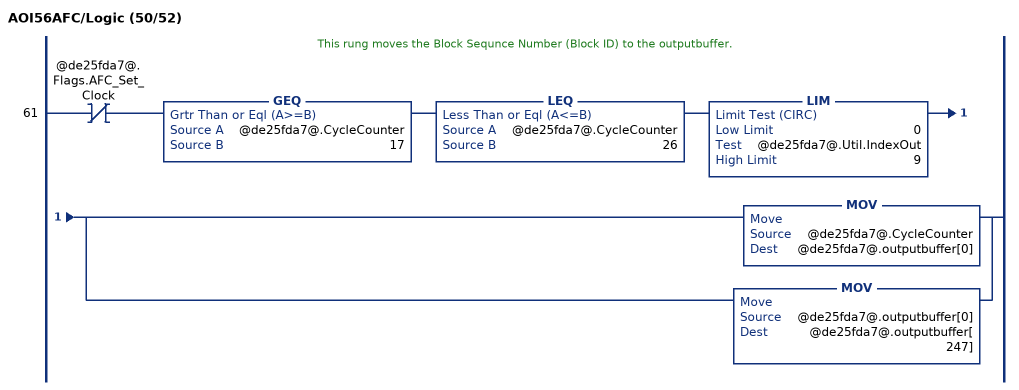
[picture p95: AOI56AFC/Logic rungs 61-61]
   // This rung moves the Block Sequnce Number (Block ID) to the outputbuffer.
   61: XIO(@de25fda7@.Flags.AFC_Set_Clock)GEQ(@de25fda7@.CycleCounter,17)LEQ(@de25fda7@.CycleCounter,26)LIM(0,@de25fda7@.Util.IndexOut,9)[MOV(@de25fda7@.CycleCounter,@de25fda7@.outputbuffer[0]) ,MOV(@de25fda7@.outputbuffer[0],@de25fda7@.outputbuffer[247]) ];
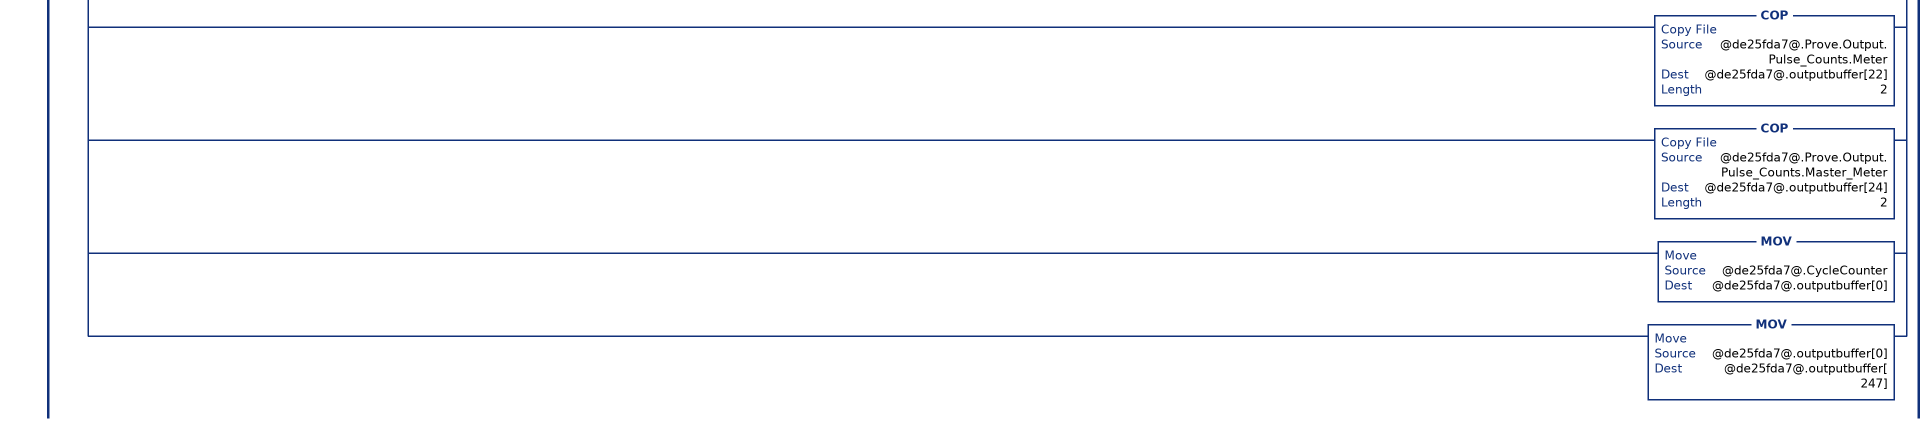
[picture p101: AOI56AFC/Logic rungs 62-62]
   // The reason to check NEQ outputbuffer[0] 5000 is to guarantee the routine will be updated one time only, so the signals can be cleared correctly once the input block is received
   62: XIO(@de25fda7@.Flags.AFC_Set_Clock)XIC(@de25fda7@.Prove.Input.Prove_Enabled)EQU(@de25fda7@.CycleCounter,5000)NEQ(@de25fda7@.outputbuffer[0],5000)[MOV(24,@de25fda7@.outputbuffer[1]) ,MOV(16#7C00,@de25fda7@.outputbuffer[2]) ,MOV(0,@de25fda7@.Util.Prover_Phase) ,XIC(@de25fda7@.Prove.Output.Process.Sequencing.Phase.Not_Selected) [OTU(@de25fda7@.Util.Prover_Phase.0) ,OTU(@de25fda7@.Util.Prover_Phase.1) ,OTU(@de25fda7@.Util.Prover_Phase.2) ] ,XIC(@de25fda7@.Prove.Output.Process.Sequencing.Phase.Active) [OTL(@de25fda7@.Util.Prover_Phase.0) ,OTU(@de25fda7@.Util.Prover_Phase.1) ,OTU(@de25fda7@.Util.Prover_Phase.2) ] ,XIC(@de25fda7@.Prove.Output.Process.Sequencing.Phase.Counting_Past_1st_Switch) [OTU(@de25fda7@.Util.Prover_Phase.0) ,OTL(@de25fda7@.Util.Prover_Phase.1) ,OTU(@de25fda7@.Util.Prover_Phase.2) ] ,XIC(@de25fda7@.Prove.Output.Process.Sequencing.Phase.Past_2nd_Switch_Fwd_Leg) [OTL(@de25fda7@.Util.Prover_Phase.0) ,OTL(@de25fda7@.Util.Prover_Phase.1) ,OTU(@de25fda7@.Util.Prover_Phase.2) ] ,XIC(@de25fda7@.Prove.Output.Process.Sequencing.Phase.Past_1st_Swith_Ret_Leg) [OTU(@de25fda7@.Util.Prover_Phase.0) ,OTU(@de25fda7@.Util.Prover_Phase.1) ,OTL(@de25fda7@.Util.Prover_Phase.2) ] ,XIC(@de25fda7@.Prove.Output.Process.Sequencing.Phase.Run_Complete) [OTL(@de25fda7@.Util.Prover_Phase.0) ,OTU(@de25fda7@.Util.Prover_Phase.1) ,OTL(@de25fda7@.Util.Prover_Phase.2) ] ,NEQ(@de25fda7@.Util.Prover_Phase,1) NEQ(@de25fda7@.Util.Prover_Phase,2) NEQ(@de25fda7@.Util.Prover_Phase,3) NEQ(@de25fda7@.Util.Prover_Phase,4) NEQ(@de25fda7@.Util.Prover_Phase,5) [OTL(@de25fda7@.Prove.Output.Process.Sequencing.Phase.Not_Selected) ,OTU(@de25fda7@.Prove.Output.Process.Sequencing.Phase.Active) ,OTU(@de25fda7@.Prove.Output.Process.Sequencing.Phase.Counting_Past_1st_Switch) ,OTU(@de25fda7@.Prove.Output.Process.Sequencing.Phase.Past_2nd_Switch_Fwd_Leg) ,OTU(@de25fda7@.Prove.Output.Process.Sequencing.Phase.Past_1st_Swith_Ret_Leg) ,OTU(@de25fda7@.Prove.Output.Process.Sequencing.Phase.Run_Complete) ,MOV(0,@de25fda7@.Util.Prover_Phase) ] ,XIC(@de25fda7@.Prove.Output.Process.Sequencing.Ball_position_ready) OTL(@de25fda7@.Util.Prover_Phase.8) ,XIC(@de25fda7@.Prove.Output.Process.Sequencing.Ball_Position_Sealed) OTL(@de25fda7@.Util.Prover_Phase.9) ,XIC(@de25fda7@.Prove.Output.Process.Sequencing.Ball_position_ready_bwd_leg) OTL(@de25fda7@.Util.Prover_Phase.10) ,XIC(@de25fda7@.Prove.Output.Process.Sequencing.Ball_Position_Sealed_Bwd_Leg) OTL(@de25fda7@.Util.Prover_Phase.11) ,MOV(@de25fda7@.Util.Prover_Phase,@de25fda7@.outputbuffer[3]) ,COP(@de25fda7@.Prove.Output.Process.Temperature,@de25fda7@.outputbuffer[4],2) ,COP(@de25fda7@.Prove.Output.Process.Outlet_Temperature,@de25fda7@.outputbuffer[6],2) ,COP(@de25fda7@.Prove.Output.Process.Switch_bar_temperature,@de25fda7@.outputbuffer[8],2) ,COP(@de25fda7@.Prove.Output.Process.Pressure,@de25fda7@.outputbuffer[10],2) ,COP(@de25fda7@.Prove.Output.Process.Outlet_Pressure,@de25fda7@.outputbuffer[12],2) ,COP(@de25fda7@.Prove.Output.Process.Prover_Density,@de25fda7@.outputbuffer[14],2) ,MOV(0,@de25fda7@.Util.Prover_Signals) ,XIC(@de25fda7@.Prove.Output.Signals.EnableProve) OTL(@de25fda7@.Util.Prover_Signals.1) ,XIC(@de25fda7@.Prove.Output.Signals.AcceptProve) OTL(@de25fda7@.Util.Prover_Signals.2) ,XIC(@de25fda7@.Prove.Output.Signals.RejectProve) OTL(@de25fda7@.Util.Prover_Signals.3) ,XIC(@de25fda7@.Prove.Output.Signals.RunStart) OTL(@de25fda7@.Util.Prover_Signals.4) ,XIC(@de25fda7@.Prove.Output.Signals.RunComplete) OTL(@de25fda7@.Util.Prover_Signals.5) ,XIC(@de25fda7@.Prove.Output.Signals.RunCancel) OTL(@de25fda7@.Util.Prover_Signals.6) ,XIC(@de25fda7@.Prove.Output.Signals.RunDelete) OTL(@de25fda7@.Util.Prover_Signals.7) ,XIC(@de25fda7@.Prove.Output.Signals.PassComplete) OTL(@de25fda7@.Util.Prover_Signals.9) ,XIC(@de25fda7@.Prove.Output.Signals.PauseProve) OTL(@de25fda7@.Util.Prover_Signals.12) ,XIC(@de25fda7@.Prove.Output.Signals.AbortProve) OTL(@de25fda7@.Util.Prover_Signals.14) ,MOV(@de25fda7@.Util.Prover_Signals,@de25fda7@.outputbuffer[16]) ,[MOV(0,@de25fda7@.Util.Prover_Controls) ,XIC(@de25fda7@.Prove.Output.Config.Enable.Auto_Accept_Prove) OTL(@de25fda7@.Util.Prover_Controls.0) ,XIC(@de25fda7@.Prove.Output.Config.Enable.Auto_Continue_Prove) OTL(@de25fda7@.Util.Prover_Controls.1) ,XIC(@de25fda7@.Prove.Output.Config.Accept.Apply_MF_Change_All_Streams) OTL(@de25fda7@.Util.Prover_Controls.13) ,XIC(@de25fda7@.Prove.Output.Config.Accept.Apply_MF_Change_Curve) OTL(@de25fda7@.Util.Prover_Controls.14) ,XIC(@de25fda7@.Prove.Output.Config.Accept.Apply_New_MF) OTL(@de25fda7@.Util.Prover_Controls.15) ,MOV(@de25fda7@.Util.Prover_Controls,@de25fda7@.outputbuffer[17]) ,MOV(@de25fda7@.Prove.Output.Config.Enable.Meter_Number,@de25fda7@.outputbuffer[18]) ,MOV(@de25fda7@.Prove.Output.Config.Accept.Requested_Interpolation_Point,@de25fda7@.outputbuffer[21]) ] ,[COP(@de25fda7@.Prove.Output.Pulse_Counts.Meter,@de25fda7@.outputbuffer[22],2) ,COP(@de25fda7@.Prove.Output.Pulse_Counts.Master_Meter,@de25fda7@.outputbuffer[24],2) ] ,[MOV(@de25fda7@.CycleCounter,@de25fda7@.outputbuffer[0]) ,MOV(@de25fda7@.outputbuffer[0],@de25fda7@.outputbuffer[247]) ] ];
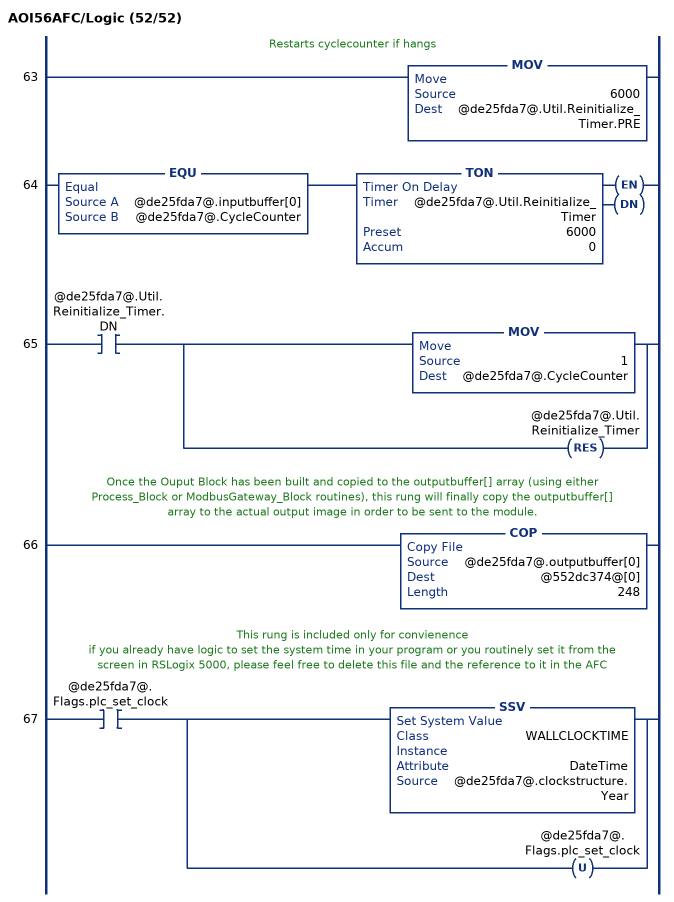
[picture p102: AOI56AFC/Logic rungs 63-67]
   // Restarts cyclecounter if hangs
   63: MOV(6000,@de25fda7@.Util.Reinitialize_Timer.PRE);
   64: EQU(@de25fda7@.inputbuffer[0],@de25fda7@.CycleCounter)TON(@de25fda7@.Util.Reinitialize_Timer,6000,0);
   65: XIC(@de25fda7@.Util.Reinitialize_Timer.DN)[MOV(1,@de25fda7@.CycleCounter) ,RES(@de25fda7@.Util.Reinitialize_Timer) ];
   // Once the Ouput Block has been built and copied to the outputbuffer[] array (using either Process_Block or ModbusGateway_Block routines), this rung will finally copy the outputbuffer[] array to the actual output image in order to be sent to the module.
   66: COP(@de25fda7@.outputbuffer[0],@552dc374@[0],248);
   // This rung is included only for convienence
   // if you already have logic to set the system time in your program or you routinely set it from the screen in RSLogix 5000, please feel free to delete this file and the reference to it in the AFC
   67: XIC(@de25fda7@.Flags.plc_set_clock)[SSV(WALLCLOCKTIME,,DateTime,@de25fda7@.clockstructure.Year) ,OTU(@de25fda7@.Flags.plc_set_clock) ];
END_ROUTINE

ROUTINE Prescan   (* ladder *)
// Power Up Handler
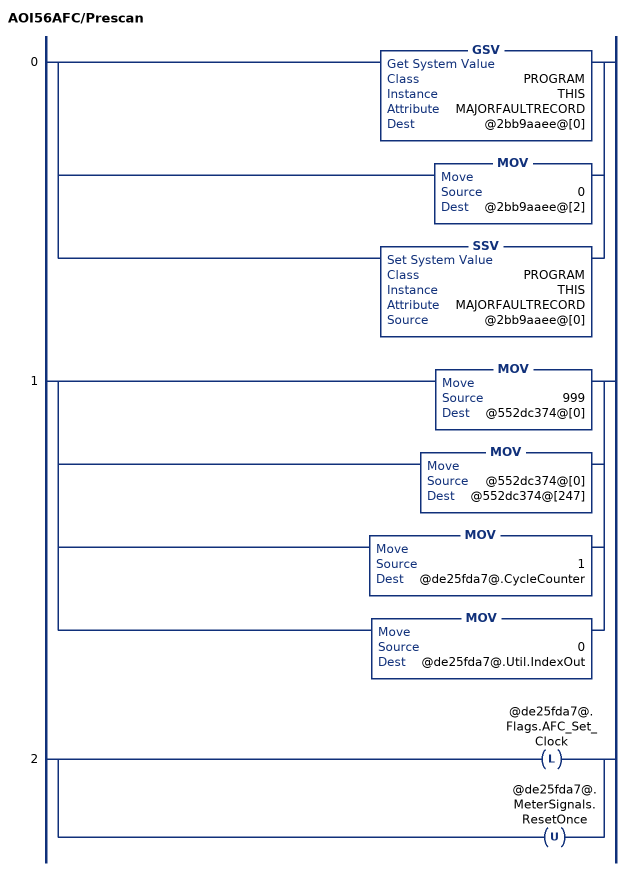
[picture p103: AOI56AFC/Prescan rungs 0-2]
   0: [GSV(PROGRAM,THIS,MAJORFAULTRECORD,@2bb9aaee@[0]) ,MOV(0,@2bb9aaee@[2]) ,SSV(PROGRAM,THIS,MAJORFAULTRECORD,@2bb9aaee@[0]) ];
   1: [MOV(999,@552dc374@[0]) ,MOV(@552dc374@[0],@552dc374@[247]) ,MOV(1,@de25fda7@.CycleCounter) ,MOV(0,@de25fda7@.Util.IndexOut) ];
   2: [OTL(@de25fda7@.Flags.AFC_Set_Clock) ,OTU(@de25fda7@.MeterSignals.ResetOnce) ];
END_ROUTINE
END_ADD_ON_INSTRUCTION

VAR_GLOBAL   (* controller tags *)
   AOI56AFC : AOI56AFC;
   AFC56 : AFC;
   Local:1:I : AB:1756_MODULE_INT_500Bytes:I:0;
   Local:1:O : AB:1756_MODULE_INT_496Bytes:O:0;
END_VAR

PROGRAM MainProgram

ROUTINE MainRoutine   (* ladder *)
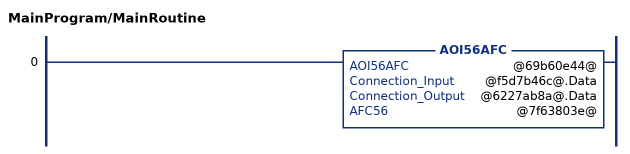
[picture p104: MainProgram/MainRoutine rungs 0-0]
   0: AOI56AFC(@69b60e44@,@f5d7b46c@.Data,@6227ab8a@.Data,@7f63803e@);
END_ROUTINE
END_PROGRAM
